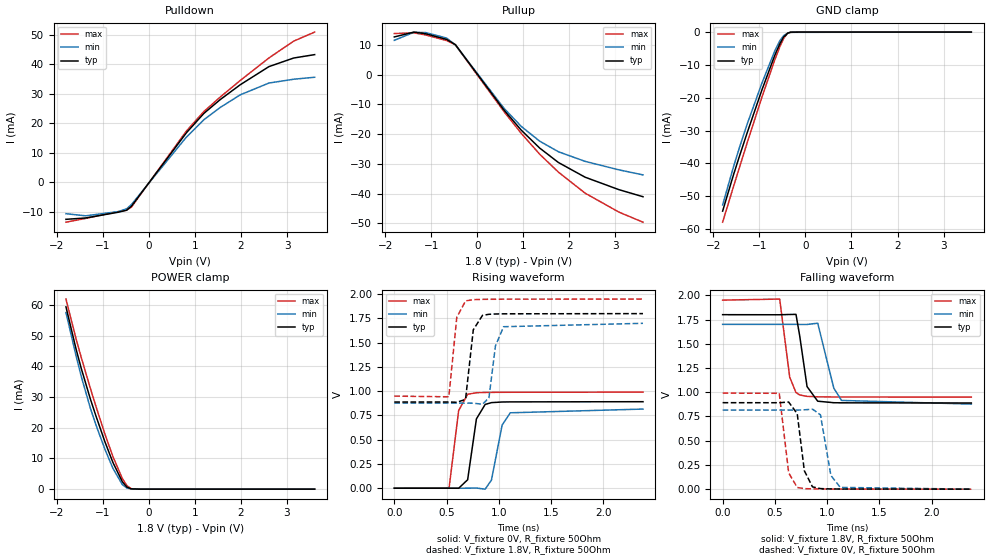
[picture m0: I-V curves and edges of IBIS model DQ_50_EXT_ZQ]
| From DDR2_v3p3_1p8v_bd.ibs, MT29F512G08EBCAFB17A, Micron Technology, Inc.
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| MODEL DQ_50_EXT_ZQ (50 Ohm Data I/O with no ODT, With ZQ Cal)
[Model]   DQ_50_EXT_ZQ
Model_type   I/O
Vinl = 650.000mV
Vinh = 1.150V
Vmeas = 900.000mV
Vref = 900.000mV
Cref = 0.0pF
Rref = 50.000Ohm
|   typ   min   max
|C_comp   1.200pF   1.100pF   1.300pF
C_comp_pullup   0.6000pF   0.5500pF   0.6500pF
C_comp_pulldown   0.6000pF   0.5500pF   0.6500pF
[Model Spec]
| Input threshold voltage corners
Vinl   0.6500V   0.6000V   0.7250V
Vinh   1.1500V   1.1000V   1.2250V
| Measurement voltage corners
Vmeas   0.9000V   0.8500V   0.9750V
| Timing spec test load voltage corners
Vref   0.9000V   0.8500V   0.9750V
| Dynamic Overshoot Parameters from ONFI4 Specification
D_overshoot_ampl_h   1.00   NA   NA
D_overshoot_ampl_l   1.00   NA   NA
D_overshoot_area_h   0.75n   NA   NA
D_overshoot_area_l   0.75n   NA   NA
[Receiver Thresholds]
Vth   =  0.900V
Vth_min  =  0.8820V
Vth_max  =  0.9180V
Vinh_ac  =  0.250V
Vinh_dc  =  0.125V
Vinl_ac  = -0.250V
Vinl_dc  = -0.125V
Tslew_ac =  5.000ns |Not specified, so set to high value
Threshold_sensitivity = 0.50
Reference_supply Pullup_ref
[Voltage Range]   1.8000V   1.7000V   1.9500V
[Pullup Reference]   1.8000V   1.7000V   1.9500V
| Junction Temperature (Ambient temp is 35C typ, 70C min, 0C max)
[Temperature Range]   50.0   85.0   0.0
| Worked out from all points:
|   slope of the pulldown table from 0 to 0.27 V, typ, clamps not added: 46.9 ohm
|   slope of the pullup table from 0 to 0.27 V, typ, clamps not added: 47.2 ohm
|   GND clamp passes 1 mA (typ) near -0.45 V on its own axis
|   POWER clamp passes 1 mA (typ) near -0.50 V on its own axis
|   falling waveform, V_fixture 1.8V, R_fixture 50Ohm: 20-80 % time 71.5ps typ, 80.7ps min, 66.5ps max; typ from 1.8 V to 0.889 V
|   rising waveform, V_fixture 0V, R_fixture 50Ohm: 20-80 % time 70.2ps typ, 87.8ps min, 56.8ps max; typ from 0 V to 0.892 V
|   rising waveform, V_fixture 1.8V, R_fixture 50Ohm: 20-80 % time 50.3ps typ, 58.8ps min, 43.2ps max; typ from 0.889 V to 1.8 V
|   falling waveform, V_fixture 0V, R_fixture 50Ohm: 20-80 % time 62.9ps typ, 71.3ps min, 56.4ps max; typ from 0.892 V to 0 V
[Pulldown]
|   Voltage   I(typ)   I(min)   I(max)
-1.8V     -12.5mA    -10.59mA   -13.47mA
-1.372V   -12.04mA   -11.31mA   -12.19mA
-667.8mV  -10.1mA    -9.89mA    -9.893mA
-482.4mV  -9.42mA    -8.93mA    -9.36mA
-380.4mV  -8.076mA   -7.521mA   -8.376mA
813mV     16.79mA    15.34mA    17.4mA
1.195V    23.42mA    21.27mA    24.05mA
1.548V    28.08mA    25.41mA    28.94mA
1.985V    33.13mA    29.71mA    34.58mA
2.608V    39.28mA    33.71mA    42.22mA
3.145V    42.19mA    35mA       47.92mA
3.6V      43.34mA    35.67mA    50.98mA
[GND Clamp]
|   Voltage   I(typ)   I(min)   I(max)
-1.8V     -54.56mA   -52.69mA   -57.93mA
-1.562V   -43.4mA    -40.96mA   -46.99mA
-1.429V   -37.59mA   -34.94mA   -41mA
-1.266V   -30.66mA   -28.02mA   -33.7mA
-947.8mV  -17.69mA   -15.6mA    -19.91mA
-667.8mV  -7.119mA   -5.754mA   -8.475mA
-553.9mV  -3.463mA   -2.548mA   -4.387mA
-474mV    -1.491mA   -1.087mA   -1.954mA
-382.4mV  -312.7uA   -236.9uA   -256.7uA
-322.2mV  -17.1uA    -73.07uA   -96.02uA
-163.8mV  -610.8nA   -69.45uA   -682.8nA
3.604V    0A         0A         0A
[Pullup]
|   Voltage   I(typ)   I(min)   I(max)
-1.8V     12.64mA    11.51mA    13.78mA
-1.373V   14.27mA    14.2mA     14.02mA
-1.117V   13.71mA    14.1mA     13.3mA
-666.1mV  11.81mA    12.27mA    11.43mA
-474mV    10.06mA    9.995mA    9.971mA
586.8mV   -12.02mA   -11.42mA   -12.54mA
959.3mV   -18.72mA   -17.45mA   -19.81mA
1.355V    -24.67mA   -22.36mA   -26.72mA
1.765V    -29.56mA   -25.94mA   -32.8mA
2.344V    -34.49mA   -29.17mA   -39.85mA
3.076V    -38.66mA   -32.01mA   -46.2mA
3.6V      -41.04mA   -33.71mA   -49.6mA
[POWER Clamp]
|   Voltage   I(typ)   I(min)   I(max)
-1.8V     59.37mA    57.52mA    61.9mA
-1.582V   45.72mA    43.5mA     49.03mA
-1.467V   39.27mA    36.67mA    42.84mA
-1.27V    29.38mA    26.39mA    32.83mA
-1.145V   23.68mA    20.79mA    26.82mA
-951.7mV  15.36mA    12.93mA    17.84mA
-780mV    8.708mA    6.801mA    10.63mA
-575.4mV  2.436mA    1.5mA      3.454mA
-473.4mV  660.1uA    347.9uA    1.122mA
-380.4mV  103uA      53.11uA    144.5uA
-178.2mV  714nA      0A         668.1nA
3.604V    0A         0A         0A
[Ramp]
R_load = 50
|   typ   min   max
dV/dt_r 5.3523E-01/7.0073E-11   4.8949E-01/8.7642E-11   5.9441E-01/5.6465E-11
dV/dt_f 5.4672E-01/7.1373E-11   4.9338E-01/8.0346E-11   6.0023E-01/6.6470E-11
[Falling Waveform]
V_fixture = 1.8V
V_fixture_min = 1.7V
V_fixture_max = 1.95V
R_fixture = 50Ohm
C_fixture = 0F
|   Time   V(typ)   V(min)   V(max)
0s        1.8V       1.7V       1.95V
546ps     1.799V     1.7V       1.961V
642ps     1.802V     1.7V       1.155V
702ps     1.803V     1.7V       997mV
738ps     1.579V     1.699V     971.9mV
808ps     1.058V     1.699V     957.3mV
910ps     907.4mV    1.712V     952.6mV
1.064ns   891.8mV    1.042V     951mV
1.138ns   890.7mV    915.3mV    950.6mV
2.38ns    888.8mV    877.7mV    949.6mV
[Rising Waveform]
V_fixture = 0V
V_fixture_min = 0V
V_fixture_max = 0V
R_fixture = 50Ohm
C_fixture = 0F
|   Time   V(typ)   V(min)   V(max)
0s        85.53uV    160.9uV    26.43uV
524ps     520.4uV    114uV      108.1uV
616ps     -68.01uV   65.56uV    801.2mV
702ps     87.56mV    527.1uV    968.7mV
786ps     715.2mV    1.802mV    984.6mV
870ps     864.1mV    -9.573mV   987.4mV
930ps     882.4mV    85.27mV    988.2mV
1.032ns   888.9mV    651.5mV    989mV
1.11ns    890.1mV    777.6mV    989.4mV
2.38ns    892.1mV    816mV      990.7mV
[Rising Waveform]
V_fixture = 1.8V
V_fixture_min = 1.7V
V_fixture_max = 1.95V
R_fixture = 50Ohm
C_fixture = 0F
|   Time   V(typ)   V(min)   V(max)
0s        888.7mV    877.5mV    949.6mV
522ps     889mV      877.5mV    942.5mV
598ps     885.9mV    877.3mV    1.761V
682ps     916.2mV    877.5mV    1.931V
756ps     1.633V     876.7mV    1.944V
844ps     1.782V     866mV      1.947V
906ps     1.793V     932.4mV    1.948V
968ps     1.796V     1.467V     1.948V
1.046ns   1.798V     1.665V     1.949V
2.38ns    1.8V       1.7V       1.95V
[Falling Waveform]
|Gnd
V_fixture = 0V
V_fixture_min = 0V
V_fixture_max = 0V
R_fixture = 50Ohm
C_fixture = 0F
|   Time   V(typ)   V(min)   V(max)
0s        892.2mV    816.1mV    990.7mV
542ps     891.7mV    816.2mV    989mV
632ps     898.8mV    816.2mV    168.4mV
714ps     778.2mV    815.6mV    17.52mV
782ps     190.2mV    818.6mV    5.884mV
860ps     23.7mV     825.1mV    3.075mV
936ps     5.966mV    767.4mV    2.07mV
1.036ns   2.469mV    141.3mV    1.466mV
1.126ns   1.606mV    18.23mV    1.119mV
2.38ns    172.1uV    287uV      83.88uV
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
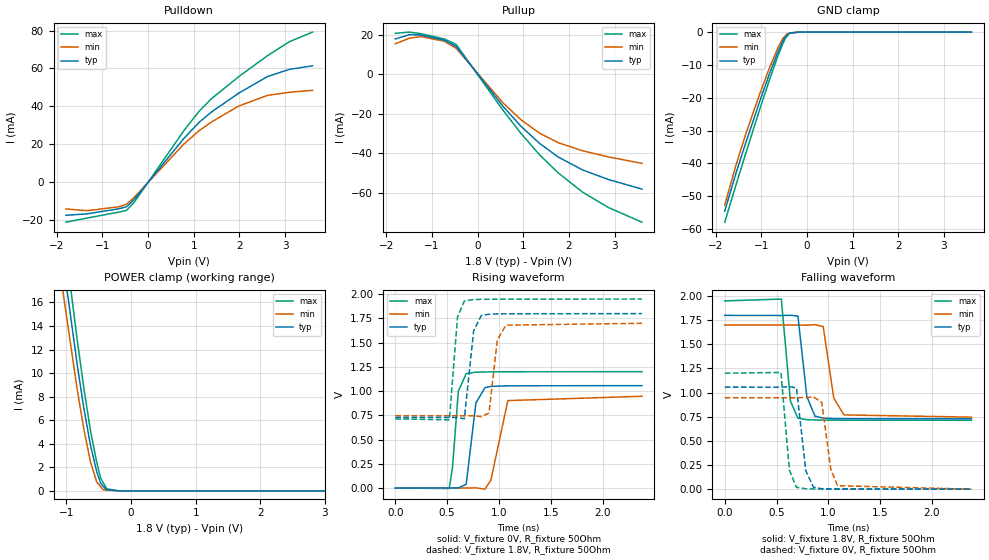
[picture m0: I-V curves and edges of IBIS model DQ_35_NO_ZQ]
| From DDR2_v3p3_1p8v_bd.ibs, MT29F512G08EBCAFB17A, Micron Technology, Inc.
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| MODEL DQ_35_NO_ZQ (35 Ohm Data I/O with no ODT, With No Cal)
[Model]   DQ_35_NO_ZQ
Model_type   I/O
Vinl = 650.000mV
Vinh = 1.150V
Vmeas = 900.000mV
Vref = 900.000mV
Cref = 0.0pF
Rref = 50.000Ohm
|   typ   min   max
|C_comp   1.200pF   1.100pF   1.300pF
C_comp_pullup   0.6000pF   0.5500pF   0.6500pF
C_comp_pulldown   0.6000pF   0.5500pF   0.6500pF
[Model Spec]
| Input threshold voltage corners
Vinl   0.6500V   0.6000V   0.7250V
Vinh   1.1500V   1.1000V   1.2250V
| Measurement voltage corners
Vmeas   0.9000V   0.8500V   0.9750V
| Timing spec test load voltage corners
Vref   0.9000V   0.8500V   0.9750V
| Dynamic Overshoot Parameters from ONFI4 Specification
D_overshoot_ampl_h   1.00   NA   NA
D_overshoot_ampl_l   1.00   NA   NA
D_overshoot_area_h   0.75n   NA   NA
D_overshoot_area_l   0.75n   NA   NA
[Receiver Thresholds]
Vth   =  0.900V
Vth_min  =  0.8820V
Vth_max  =  0.9180V
Vinh_ac  =  0.250V
Vinh_dc  =  0.125V
Vinl_ac  = -0.250V
Vinl_dc  = -0.125V
Tslew_ac =  5.000ns |Not specified, so set to high value
Threshold_sensitivity = 0.50
Reference_supply Pullup_ref
[Voltage Range]   1.8000V   1.7000V   1.9500V
[Pullup Reference]   1.8000V   1.7000V   1.9500V
| Junction Temperature (Ambient temp is 35C typ, 70C min, 0C max)
[Temperature Range]   50.0   85.0   0.0
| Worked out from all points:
|   slope of the pulldown table from 0 to 0.27 V, typ, clamps not added: 33.1 ohm
|   slope of the pullup table from 0 to 0.27 V, typ, clamps not added: 33.4 ohm
|   GND clamp passes 1 mA (typ) near -0.44 V on its own axis
|   POWER clamp passes 1 mA (typ) near -0.50 V on its own axis
|   falling waveform, V_fixture 1.8V, R_fixture 50Ohm: 20-80 % time 62.7ps typ, 74.2ps min, 53.7ps max; typ from 1.8 V to 0.728 V
|   rising waveform, V_fixture 0V, R_fixture 50Ohm: 20-80 % time 61.4ps typ, 78.4ps min, 49.4ps max; typ from 0 V to 1.06 V
|   rising waveform, V_fixture 1.8V, R_fixture 50Ohm: 20-80 % time 44.4ps typ, 52.3ps min, 38ps max; typ from 0.728 V to 1.8 V
|   falling waveform, V_fixture 0V, R_fixture 50Ohm: 20-80 % time 58ps typ, 68.5ps min, 50.1ps max; typ from 1.06 V to 0 V
[Pulldown]
|   Voltage   I(typ)   I(min)   I(max)
-1.8V     -17.7mA    -14.36mA   -21.34mA
-1.331V   -16.91mA   -15.24mA   -19.12mA
-630.4mV  -14.2mA    -13.16mA   -15.98mA
-473.4mV  -13.2mA    -11.88mA   -15.08mA
-313.2mV  -9.601mA   -8.423mA   -11.12mA
776mV     22.77mA    19.79mA    26.8mA
1.116V    31.44mA    27.04mA    37.31mA
1.394V    37.03mA    31.74mA    44.1mA
1.985V    46.91mA    40.09mA    55.61mA
2.614V    55.67mA    45.71mA    66.71mA
3.092V    59.47mA    47.35mA    74.09mA
3.6V      61.35mA    48.4mA     79.18mA
[GND Clamp]
|   Voltage   I(typ)   I(min)   I(max)
-1.8V     -54.56mA   -52.69mA   -57.93mA
-1.554V   -43.01mA   -40.54mA   -46.59mA
-1.336V   -33.61mA   -30.93mA   -36.81mA
-1.036V   -21.2mA    -18.93mA   -23.66mA
-829.3mV  -13.08mA   -11.23mA   -14.95mA
-630.4mV  -5.889mA   -4.612mA   -7.067mA
-531.8mV  -2.931mA   -2.046mA   -3.69mA
-472.1mV  -1.487mA   -1.111mA   -1.902mA
-431.5mV  -903.3uA   -483.2uA   -1.222mA
-378mV    -285.6uA   -293uA     -327uA
-178.2mV  -2.719uA   -1.561uA   -751.9nA
3.604V    0A         0A         0A
[Pullup]
|   Voltage   I(typ)   I(min)   I(max)
-1.8V     17.84mA    15.4mA     20.68mA
-1.492V   20.03mA    18.23mA    21.32mA
-1.242V   19.84mA    19.05mA    20.53mA
-729mV    17.17mA    16.69mA    17.85mA
-472.1mV  14.17mA    13.21mA    15.18mA
564.7mV   -16.42mA   -14.66mA   -18.41mA
957.4mV   -26.46mA   -23.16mA   -30.13mA
1.359V    -35mA      -29.83mA   -40.79mA
1.765V    -41.86mA   -34.62mA   -49.89mA
2.301V    -48.43mA   -38.72mA   -59.68mA
2.866V    -53.25mA   -41.82mA   -67.44mA
3.6V      -58.12mA   -45.09mA   -74.85mA
[POWER Clamp]
|   Voltage   I(typ)   I(min)   I(max)
-1.8V     59.37mA    57.52mA    61.9mA
-1.055V   19.69mA    17mA       22.54mA
-1.034V   18.79mA    16.14mA    21.56mA
-829.3mV  10.55mA    8.462mA    12.64mA
-729mV    6.964mA    5.185mA    8.66mA
-630.4mV  3.937mA    2.522mA    5.201mA
-531mV    1.618mA    753.4uA    2.409mA
-472.1mV  669.5uA    367.5uA    1.103mA
-431.5mV  391.1uA    106.3uA    708.2uA
-376.5mV  100.3uA    62.6uA     180.1uA
-178.2mV  0A         501.6nA    561.5nA
3.604V    0A         0A         0A
[Ramp]
R_load = 50
|   typ   min   max
dV/dt_r 6.3425E-01/6.1156E-11   5.6816E-01/7.7489E-11   7.2087E-01/4.9145E-11
dV/dt_f 6.4316E-01/6.2537E-11   5.7228E-01/7.3865E-11   7.4183E-01/5.3549E-11
[Falling Waveform]
V_fixture = 1.8V
V_fixture_min = 1.7V
V_fixture_max = 1.95V
R_fixture = 50Ohm
C_fixture = 0F
|   Time   V(typ)   V(min)   V(max)
0s        1.8V       1.7V       1.95V
546ps     1.799V     1.7V       1.969V
634ps     1.801V     1.7V       911.8mV
706ps     1.793V     1.7V       735.2mV
792ps     960.4mV    1.698V     719.1mV
870ps     756.6mV    1.704V     716.6mV
950ps     735.4mV    1.684V     715.5mV
1.052ns   730.9mV    943.2mV    714.8mV
1.15ns    729.7mV    769.2mV    714.4mV
2.38ns    728.1mV    746.1mV    713.6mV
[Rising Waveform]
V_fixture = 0V
V_fixture_min = 0V
V_fixture_max = 0V
R_fixture = 50Ohm
C_fixture = 0F
|   Time   V(typ)   V(min)   V(max)
0s        77.71uV    151uV      22.52uV
520ps     407uV      107.6uV    -4.55mV
552ps     1.505mV    105uV      213.2mV
608ps     1.597mV    70.13uV    998.6mV
684ps     38.38mV    162.8uV    1.181V
778ps     879.3mV    2.272mV    1.196V
866ps     1.037V     -11.36mV   1.198V
922ps     1.049V     81.9mV     1.199V
1.086ns   1.055V     902.5mV    1.2V
2.38ns    1.057V     947.1mV    1.201V
[Rising Waveform]
V_fixture = 1.8V
V_fixture_min = 1.7V
V_fixture_max = 1.95V
R_fixture = 50Ohm
C_fixture = 0F
|   Time   V(typ)   V(min)   V(max)
0s        728mV      746mV      713.6mV
522ps     728.3mV    746mV      704.2mV
600ps     726.8mV    745.9mV    1.764V
666ps     715.3mV    745.9mV    1.93V
756ps     1.623V     746.3mV    1.945V
830ps     1.78V      737.5mV    1.947V
904ps     1.794V     774.2mV    1.948V
984ps     1.797V     1.527V     1.948V
1.068ns   1.798V     1.681V     1.949V
2.38ns    1.8V       1.7V       1.95V
[Falling Waveform]
|Gnd
V_fixture = 0V
V_fixture_min = 0V
V_fixture_max = 0V
R_fixture = 50Ohm
C_fixture = 0F
|   Time   V(typ)   V(min)   V(max)
0s        1.057V     947.2mV    1.201V
542ps     1.056V     947.3mV    1.209V
624ps     1.062V     947.3mV    198.2mV
692ps     1.05V      946.9mV    19.04mV
782ps     191.3mV    948.4mV    4.38mV
856ps     20.36mV    956.1mV    2.688mV
936ps     4.976mV    897.5mV    1.813mV
1.024ns   2.434mV    204.2mV    1.316mV
1.088ns   1.772mV    35.8mV     1.078mV
2.38ns    156.7uV    268.8uV    64.47uV
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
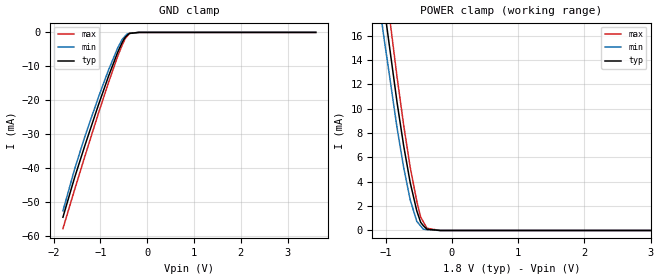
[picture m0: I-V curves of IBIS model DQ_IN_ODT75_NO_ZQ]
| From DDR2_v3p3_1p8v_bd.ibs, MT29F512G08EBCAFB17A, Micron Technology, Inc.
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| MODEL DQ_IN_ODT75_NO_ZQ (Data Input with 75ohm ODT, With No Cal)
[Model]   DQ_IN_ODT75_NO_ZQ
Model_type   Input
Vinl = 650.000mV
Vinh = 1.150V
|   typ   min   max
|C_comp   1.136pF   1.026pF   1.246pF
C_comp_power_clamp   0.5680pF   0.5130pF   0.6230pF
C_comp_gnd_clamp   0.5680pF   0.5130pF   0.6230pF
| Note: C_comp changes when the ODT circuit is enabled.
[Model Spec]
| Input threshold voltage corners
Vinl   0.6500V   0.6000V   0.7250V
Vinh   1.1500V   1.1000V   1.2250V
| Dynamic Overshoot Parameters from ONFI4 Specification
D_overshoot_ampl_h   1.00   NA   NA
D_overshoot_ampl_l   1.00   NA   NA
D_overshoot_area_h   0.75n   NA   NA
D_overshoot_area_l   0.75n   NA   NA
[Receiver Thresholds]
Vth   =  0.900V
Vth_min  =  0.8820V
Vth_max  =  0.9180V
Vinh_ac  =  0.250V
Vinh_dc  =  0.125V
Vinl_ac  = -0.250V
Vinl_dc  = -0.125V
Tslew_ac =  5.000ns |Not specified, so set to high value
Threshold_sensitivity = 0.50
Reference_supply Power_clamp_ref
[Voltage Range]   1.8000V   1.7000V   1.9500V
[POWER Clamp Reference]   1.8000V   1.7000V   1.9500V
| Junction Temperature (Ambient temp is 35C typ, 70C min, 0C max)
[Temperature Range]   50.0   85.0   0.0
[Add Submodel]
| Submodel Name   Mode
75ohm_ODT_NO_ZQ   Non-Driving
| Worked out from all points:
|   GND clamp passes 1 mA (typ) near -0.44 V on its own axis
|   POWER clamp passes 1 mA (typ) near -0.50 V on its own axis
[GND Clamp]
|   Voltage   I(typ)   I(min)   I(max)
-1.8V     -54.56mA   -52.69mA   -57.93mA
-1.554V   -43.01mA   -40.54mA   -46.59mA
-1.336V   -33.61mA   -30.93mA   -36.81mA
-1.036V   -21.2mA    -18.93mA   -23.66mA
-829.3mV  -13.08mA   -11.23mA   -14.95mA
-630.4mV  -5.889mA   -4.612mA   -7.067mA
-531.8mV  -2.931mA   -2.046mA   -3.69mA
-472.1mV  -1.487mA   -1.111mA   -1.902mA
-431.5mV  -903.3uA   -483.2uA   -1.222mA
-378mV    -285.6uA   -293uA     -327uA
-178.2mV  -2.719uA   -1.561uA   -751.9nA
3.604V    0A         0A         0A
[POWER Clamp]
|   Voltage   I(typ)   I(min)   I(max)
-1.8V     59.37mA    57.52mA    61.9mA
-1.055V   19.69mA    17mA       22.54mA
-1.034V   18.79mA    16.14mA    21.56mA
-829.3mV  10.55mA    8.462mA    12.64mA
-729mV    6.964mA    5.185mA    8.66mA
-630.4mV  3.937mA    2.522mA    5.201mA
-531mV    1.618mA    753.4uA    2.409mA
-472.1mV  669.5uA    367.5uA    1.103mA
-431.5mV  391.1uA    106.3uA    708.2uA
-376.5mV  100.3uA    62.6uA     180.1uA
-178.2mV  0A         501.6nA    561.5nA
3.604V    0A         0A         0A
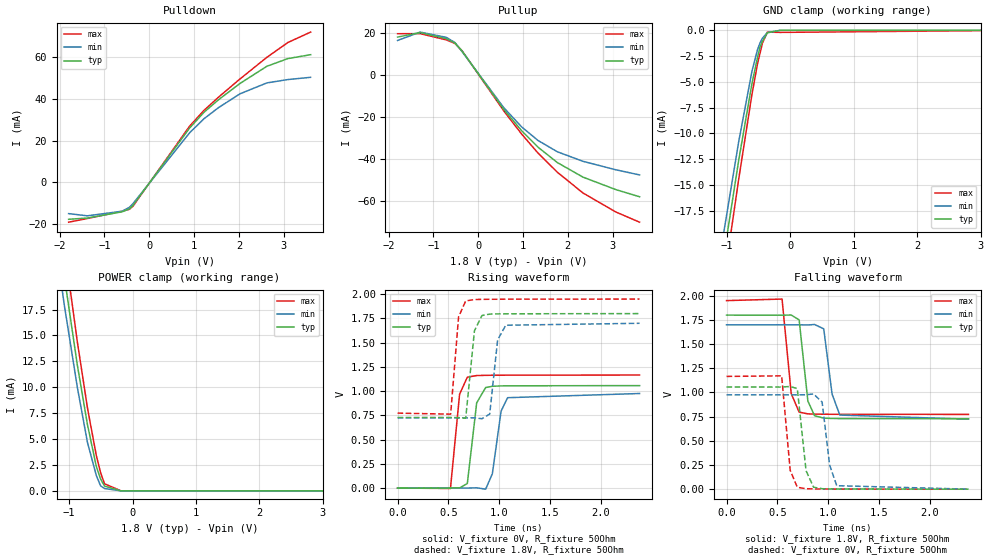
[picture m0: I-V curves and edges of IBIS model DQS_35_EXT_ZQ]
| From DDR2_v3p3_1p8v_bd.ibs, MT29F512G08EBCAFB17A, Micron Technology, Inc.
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| MODEL DQS_35_EXT_ZQ (35 Ohm Data Strobe I/O with no ODT, With ZQ Cal)
[Model]   DQS_35_EXT_ZQ
Model_type   I/O
Vinl = 650.000mV
Vinh = 1.150V
Vmeas = 900.000mV
Vref = 900.000mV
Cref = 0.0pF
Rref = 50.000Ohm
|   typ   min   max
|C_comp   1.200pF   1.100pF   1.300pF
C_comp_pullup   0.6000pF   0.5500pF   0.6500pF
C_comp_pulldown   0.6000pF   0.5500pF   0.6500pF
[Model Spec]
| Input threshold voltage corners
Vinl   0.6500V   0.6000V   0.7250V
Vinh   1.1500V   1.1000V   1.2250V
| Measurement voltage corners
Vmeas   0.9000V   0.8500V   0.9750V
| Timing spec test load voltage corners
Vref   0.9000V   0.8500V   0.9750V
| Dynamic Overshoot Parameters from ONFI4 Specification
D_overshoot_ampl_h   1.00   NA   NA
D_overshoot_ampl_l   1.00   NA   NA
D_overshoot_area_h   0.75n   NA   NA
D_overshoot_area_l   0.75n   NA   NA
[Receiver Thresholds]
|Vth   =  0.900V
|Vth_min  =  0.8820V
|Vth_max  =  0.9180V
|Vinh_ac  =  0.250V
|Vinh_dc  =  0.125V
|Vinl_ac  = -0.250V
|Vinl_dc  = -0.125V
|Tslew_ac =  5.000ns |Not specified, so set to high value
|Threshold_sensitivity = 0.50
|Reference_supply Pullup_ref
Vcross_low   = 0.725V
Vcross_high  = 1.075V
Vdiff_ac   = 500mV
Vdiff_dc   = 250mV
Tdiffslew_ac = 10.000ns |Not specified, so set to high value
[Voltage Range]   1.8000V   1.7000V   1.9500V
[Pullup Reference]   1.8000V   1.7000V   1.9500V
| Junction Temperature (Ambient temp is 35C typ, 70C min, 0C max)
[Temperature Range]   50.0   85.0   0.0
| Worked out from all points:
|   slope of the pulldown table from 0 to 0.27 V, typ, clamps not added: 33.1 ohm
|   slope of the pullup table from 0 to 0.27 V, typ, clamps not added: 33.4 ohm
|   GND clamp passes 1 mA (typ) near -0.44 V on its own axis
|   POWER clamp passes 1 mA (typ) near -0.50 V on its own axis
|   falling waveform, V_fixture 1.8V, R_fixture 50Ohm: 20-80 % time 63.1ps typ, 71ps min, 58.7ps max; typ from 1.8 V to 0.728 V
|   rising waveform, V_fixture 0V, R_fixture 50Ohm: 20-80 % time 61.4ps typ, 75.9ps min, 51.1ps max; typ from 0 V to 1.06 V
|   rising waveform, V_fixture 1.8V, R_fixture 50Ohm: 20-80 % time 44.4ps typ, 51.4ps min, 39.1ps max; typ from 0.728 V to 1.8 V
|   falling waveform, V_fixture 0V, R_fixture 50Ohm: 20-80 % time 58ps typ, 66.3ps min, 52ps max; typ from 1.06 V to 0 V
[Pulldown]
|   Voltage   I(typ)   I(min)   I(max)
-1.8V     -17.7mA    -14.98mA   -19.1mA
-1.382V   -17.11mA   -16.04mA   -17.33mA
-608.3mV  -14.13mA   -13.83mA   -13.84mA
-442.8mV  -12.67mA   -11.96mA   -12.9mA
-362.9mV  -10.97mA   -10.16mA   -11.4mA
901.3mV   26.16mA    23.87mA    27.08mA
1.224V    33.76mA    30.65mA    34.67mA
1.548V    39.76mA    35.96mA    41mA
2.021V    47.48mA    42.52mA    49.64mA
2.623V    55.77mA    47.79mA    60.05mA
3.092V    59.47mA    49.4mA     67.19mA
3.6V      61.35mA    50.48mA    72.2mA
[GND Clamp]
|   Voltage   I(typ)   I(min)   I(max)
-1.8V     -54.56mA   -52.69mA   -57.93mA
-1.548V   -42.78mA   -40.31mA   -46.36mA
-1.327V   -33.25mA   -30.57mA   -36.44mA
-1.077V   -22.86mA   -20.51mA   -25.43mA
-817.4mV  -12.62mA   -10.81mA   -14.45mA
-608.3mV  -5.168mA   -3.972mA   -6.219mA
-520.8mV  -2.645mA   -1.885mA   -3.256mA
-480.6mV  -1.611mA   -1.209mA   -2.217mA
-442.8mV  -1.066mA   -762.6uA   -1.241mA
-364.8mV  -238.2uA   -221uA     -173.5uA
-163.8mV  -972.9nA   0A         -201.1uA
3.604V    0A         0A         0A
[Pullup]
|   Voltage   I(typ)   I(min)   I(max)
-1.8V     17.84mA    16.24mA    19.44mA
-1.297V   20mA       20.22mA    19.5mA
-713.7mV  17.06mA    17.72mA    16.51mA
-520.8mV  15.03mA    15.26mA    14.81mA
-362.9mV  11.26mA    10.99mA    11.39mA
574.9mV   -16.7mA    -15.87mA   -17.41mA
971mV     -26.78mA   -24.94mA   -28.36mA
1.333V    -34.51mA   -31.33mA   -37.32mA
1.765V    -41.86mA   -36.72mA   -46.45mA
2.338V    -48.79mA   -41.26mA   -56.33mA
3.067V    -54.69mA   -45.27mA   -65.33mA
3.6V      -58.12mA   -47.73mA   -70.22mA
[POWER Clamp]
|   Voltage   I(typ)   I(min)   I(max)
-1.8V     59.37mA    57.52mA    61.9mA
-1.585V   45.91mA    43.7mA     49.21mA
-1.437V   37.69mA    35mA       41.3mA
-1.276V   29.7mA     26.71mA    33.17mA
-1.077V   20.68mA    17.92mA    23.6mA
-871.2mV  12.13mA    9.982mA    14.37mA
-712mV    6.399mA    4.675mA    8.008mA
-572.4mV  2.368mA    1.496mA    3.424mA
-504.6mV  1.145mA    486.6uA    1.765mA
-442.8mV  468.7uA    231.8uA    685.7uA
-178.2mV  0A         0A         0A
3.604V    0A         0A         0A
[Ramp]
R_load = 50
|   typ   min   max
dV/dt_r 6.3425E-01/6.1156E-11   5.8519E-01/7.5395E-11   6.9956E-01/5.0656E-11
dV/dt_f 6.4316E-01/6.2537E-11   5.8549E-01/7.0593E-11   7.0614E-01/5.8457E-11
[Falling Waveform]
V_fixture = 1.8V
V_fixture_min = 1.7V
V_fixture_max = 1.95V
R_fixture = 50Ohm
C_fixture = 0F
|   Time   V(typ)   V(min)   V(max)
0s        1.8V       1.7V       1.95V
546ps     1.799V     1.7V       1.966V
636ps     1.801V     1.7V       988.7mV
714ps     1.751V     1.7V       796.6mV
800ps     911mV      1.698V     778.8mV
866ps     759.3mV    1.703V     776.4mV
956ps     734.8mV    1.658V     775.1mV
1.038ns   731.2mV    983.7mV    774.4mV
1.114ns   730mV      766.3mV    774.1mV
2.38ns    728.1mV    724.1mV    773.1mV
[Rising Waveform]
V_fixture = 0V
V_fixture_min = 0V
V_fixture_max = 0V
R_fixture = 50Ohm
C_fixture = 0F
|   Time   V(typ)   V(min)   V(max)
0s        77.71uV    148.8uV    25.96uV
520ps     407uV      108.2uV    -4.379mV
610ps     1.34mV     67.12uV    969.2mV
686ps     46.66mV    216.9uV    1.144V
778ps     879.3mV    2.279mV    1.161V
866ps     1.037V     -11.54mV   1.163V
932ps     1.05V      146.7mV    1.164V
1.018ns   1.054V     793.6mV    1.164V
1.082ns   1.055V     932.3mV    1.165V
2.38ns    1.057V     975.5mV    1.166V
[Rising Waveform]
V_fixture = 1.8V
V_fixture_min = 1.7V
V_fixture_max = 1.95V
R_fixture = 50Ohm
C_fixture = 0F
|   Time   V(typ)   V(min)   V(max)
0s        728mV      724mV      773.1mV
522ps     728.3mV    724mV      762.5mV
600ps     726.8mV    723.8mV    1.766V
670ps     720.2mV    723.9mV    1.931V
756ps     1.623V     724.3mV    1.945V
830ps     1.78V      715.4mV    1.947V
906ps     1.795V     763.3mV    1.948V
984ps     1.797V     1.529V     1.948V
1.064ns   1.798V     1.68V      1.949V
2.38ns    1.8V       1.7V       1.95V
[Falling Waveform]
|Gnd
V_fixture = 0V
V_fixture_min = 0V
V_fixture_max = 0V
R_fixture = 50Ohm
C_fixture = 0F
|   Time   V(typ)   V(min)   V(max)
0s        1.057V     975.6mV    1.166V
542ps     1.056V     975.7mV    1.172V
626ps     1.062V     975.7mV    195mV
696ps     1.04V      975.2mV    19.77mV
782ps     191.3mV    977mV      4.814mV
856ps     20.36mV    984.4mV    2.815mV
940ps     4.792mV    900.3mV    1.923mV
1.014ns   2.602mV    250.1mV    1.443mV
1.084ns   1.808mV    35.79mV    1.154mV
2.38ns    156.7uV    262.2uV    75.18uV
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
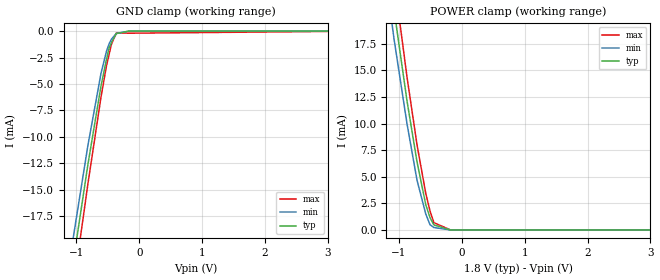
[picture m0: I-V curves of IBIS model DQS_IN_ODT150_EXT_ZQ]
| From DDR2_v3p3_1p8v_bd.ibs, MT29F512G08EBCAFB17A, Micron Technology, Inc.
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| MODEL DQS_IN_ODT150_EXT_ZQ (Data Strobe Input with 150ohm ODT, With ZQ Cal)
[Model]   DQS_IN_ODT150_EXT_ZQ
Model_type   Input
Vinl = 650.000mV
Vinh = 1.150V
|   typ   min   max
|C_comp   1.166pF   1.062pF   1.271pF
C_comp_power_clamp   0.5830pF   0.5310pF   0.6355pF
C_comp_gnd_clamp   0.5830pF   0.5310pF   0.6355pF
| Note: C_comp changes when the ODT circuit is enabled.
[Model Spec]
| Input threshold voltage corners
Vinl   0.6500V   0.6000V   0.7250V
Vinh   1.1500V   1.1000V   1.2250V
| Dynamic Overshoot Parameters from ONFI4 Specification
D_overshoot_ampl_h   1.00   NA   NA
D_overshoot_ampl_l   1.00   NA   NA
D_overshoot_area_h   0.75n   NA   NA
D_overshoot_area_l   0.75n   NA   NA
[Receiver Thresholds]
|Vth   =  0.900V
|Vth_min  =  0.8820V
|Vth_max  =  0.9180V
|Vinh_ac  =  0.250V
|Vinh_dc  =  0.125V
|Vinl_ac  = -0.250V
|Vinl_dc  = -0.125V
|Tslew_ac =  5.000ns |Not specified, so set to high value
|Threshold_sensitivity = 0.50
|Reference_supply Power_clamp_ref
Vcross_low   = 0.725V
Vcross_high  = 1.075V
Vdiff_ac   = 500mV
Vdiff_dc   = 250mV
Tdiffslew_ac = 10.000ns |Not specified, so set to high value
[Voltage Range]   1.8000V   1.7000V   1.9500V
[POWER Clamp Reference]   1.8000V   1.7000V   1.9500V
| Junction Temperature (Ambient temp is 35C typ, 70C min, 0C max)
[Temperature Range]   50.0   85.0   0.0
[Add Submodel]
| Submodel Name   Mode
150ohm_ODT_EXT_ZQ   Non-Driving
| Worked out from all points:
|   GND clamp passes 1 mA (typ) near -0.44 V on its own axis
|   POWER clamp passes 1 mA (typ) near -0.50 V on its own axis
[GND Clamp]
|   Voltage   I(typ)   I(min)   I(max)
-1.8V     -54.56mA   -52.69mA   -57.93mA
-1.548V   -42.78mA   -40.31mA   -46.36mA
-1.327V   -33.25mA   -30.57mA   -36.44mA
-1.077V   -22.86mA   -20.51mA   -25.43mA
-817.4mV  -12.62mA   -10.81mA   -14.45mA
-608.3mV  -5.168mA   -3.972mA   -6.219mA
-520.8mV  -2.645mA   -1.885mA   -3.256mA
-480.6mV  -1.611mA   -1.209mA   -2.217mA
-442.8mV  -1.066mA   -762.6uA   -1.241mA
-364.8mV  -238.2uA   -221uA     -173.5uA
-163.8mV  -972.9nA   0A         -201.1uA
3.604V    0A         0A         0A
[POWER Clamp]
|   Voltage   I(typ)   I(min)   I(max)
-1.8V     59.37mA    57.52mA    61.9mA
-1.585V   45.91mA    43.7mA     49.21mA
-1.437V   37.69mA    35mA       41.3mA
-1.276V   29.7mA     26.71mA    33.17mA
-1.077V   20.68mA    17.92mA    23.6mA
-871.2mV  12.13mA    9.982mA    14.37mA
-712mV    6.399mA    4.675mA    8.008mA
-572.4mV  2.368mA    1.496mA    3.424mA
-504.6mV  1.145mA    486.6uA    1.765mA
-442.8mV  468.7uA    231.8uA    685.7uA
-178.2mV  0A         0A         0A
3.604V    0A         0A         0A
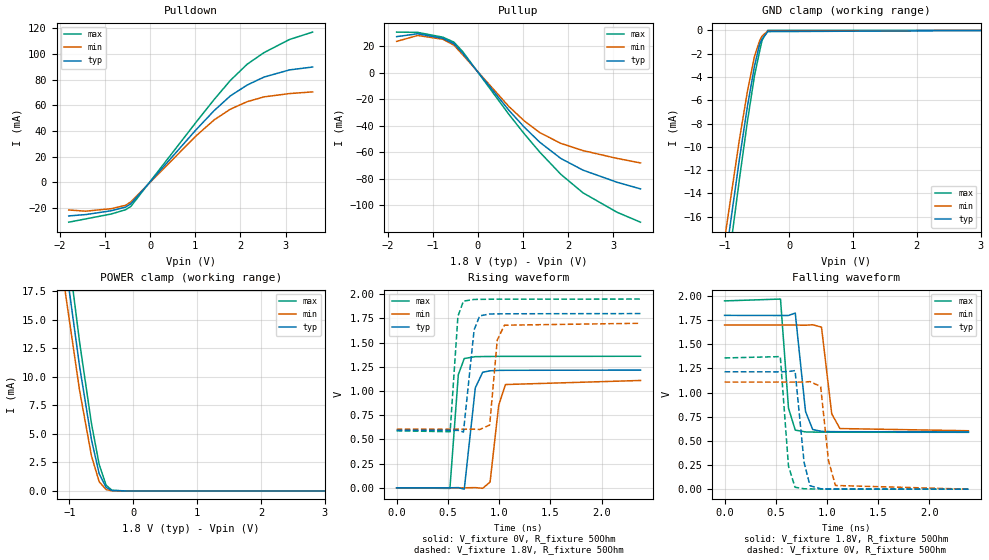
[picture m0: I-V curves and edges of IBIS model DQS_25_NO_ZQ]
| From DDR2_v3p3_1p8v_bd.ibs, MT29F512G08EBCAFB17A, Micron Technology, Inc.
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| MODEL DQS_25_NO_ZQ (25 Ohm Data Strobe I/O with no ODT, With No Cal)
[Model]   DQS_25_NO_ZQ
Model_type   I/O
Vinl = 650.000mV
Vinh = 1.150V
Vmeas = 900.000mV
Vref = 900.000mV
Cref = 0.0pF
Rref = 50.000Ohm
|   typ   min   max
|C_comp   1.200pF   1.100pF   1.300pF
C_comp_pullup   0.6000pF   0.5500pF   0.6500pF
C_comp_pulldown   0.6000pF   0.5500pF   0.6500pF
[Model Spec]
| Input threshold voltage corners
Vinl   0.6500V   0.6000V   0.7250V
Vinh   1.1500V   1.1000V   1.2250V
| Measurement voltage corners
Vmeas   0.9000V   0.8500V   0.9750V
| Timing spec test load voltage corners
Vref   0.9000V   0.8500V   0.9750V
| Dynamic Overshoot Parameters from ONFI4 Specification
D_overshoot_ampl_h   1.00   NA   NA
D_overshoot_ampl_l   1.00   NA   NA
D_overshoot_area_h   0.75n   NA   NA
D_overshoot_area_l   0.75n   NA   NA
[Receiver Thresholds]
|Vth   =  0.900V
|Vth_min  =  0.8820V
|Vth_max  =  0.9180V
|Vinh_ac  =  0.250V
|Vinh_dc  =  0.125V
|Vinl_ac  = -0.250V
|Vinl_dc  = -0.125V
|Tslew_ac =  5.000ns |Not specified, so set to high value
|Threshold_sensitivity = 0.50
|Reference_supply Pullup_ref
Vcross_low   = 0.725V
Vcross_high  = 1.075V
Vdiff_ac   = 500mV
Vdiff_dc   = 250mV
Tdiffslew_ac = 10.000ns |Not specified, so set to high value
[Voltage Range]   1.8000V   1.7000V   1.9500V
[Pullup Reference]   1.8000V   1.7000V   1.9500V
| Junction Temperature (Ambient temp is 35C typ, 70C min, 0C max)
[Temperature Range]   50.0   85.0   0.0
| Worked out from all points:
|   slope of the pulldown table from 0 to 0.27 V, typ, clamps not added: 24.4 ohm
|   slope of the pullup table from 0 to 0.27 V, typ, clamps not added: 23.5 ohm
|   GND clamp passes 1 mA (typ) near -0.44 V on its own axis
|   POWER clamp passes 1 mA (typ) near -0.50 V on its own axis
|   falling waveform, V_fixture 1.8V, R_fixture 50Ohm: 20-80 % time 56.2ps typ, 65.1ps min, 49.5ps max; typ from 1.8 V to 0.594 V
|   rising waveform, V_fixture 0V, R_fixture 50Ohm: 20-80 % time 51ps typ, 63.2ps min, 43.2ps max; typ from 0 V to 1.22 V
|   rising waveform, V_fixture 1.8V, R_fixture 50Ohm: 20-80 % time 39.1ps typ, 44.9ps min, 36ps max; typ from 0.593 V to 1.8 V
|   falling waveform, V_fixture 0V, R_fixture 50Ohm: 20-80 % time 56.5ps typ, 64.5ps min, 50.7ps max; typ from 1.22 V to 0 V
[Pulldown]
|   Voltage   I(typ)   I(min)   I(max)
-1.8V     -26.36mA   -21.71mA   -31.25mA
-1.426V   -25.32mA   -22.66mA   -28.71mA
-858.6mV  -22.32mA   -20.7mA    -24.85mA
-540.3mV  -19.51mA   -18.09mA   -21.53mA
-423.3mV  -16.83mA   -15.34mA   -18.93mA
1.018V    40.81mA    36.06mA    46.68mA
1.418V    55.76mA    48.52mA    64.39mA
1.778V    67.29mA    56.91mA    79.34mA
2.153V    75.82mA    62.82mA    92.08mA
2.525V    82mA       66.54mA    101.1mA
3.087V    87.58mA    69.12mA    111.3mA
3.6V      89.84mA    70.44mA    117.1mA
[GND Clamp]
|   Voltage   I(typ)   I(min)   I(max)
-1.8V     -54.56mA   -52.69mA   -57.93mA
-1.655V   -47.63mA   -45.42mA   -51.23mA
-1.426V   -37.44mA   -34.79mA   -40.84mA
-1.251V   -30.05mA   -27.42mA   -33.05mA
-1.033V   -21.1mA    -18.84mA   -23.56mA
-776.6mV  -11.06mA   -9.371mA   -12.78mA
-652.5mV  -6.574mA   -5.277mA   -7.868mA
-540.3mV  -3.062mA   -2.234mA   -3.888mA
-460.8mV  -1.227mA   -897.2uA   -1.819mA
-421.4mV  -732.2uA   -483.9uA   -851.1uA
-331.7mV  -111.2uA   -68.27uA   0A
3.604V    0A         0A         0A
[Pullup]
|   Voltage   I(typ)   I(min)   I(max)
-1.8V     27.24mA    23.66mA    30.68mA
-1.334V   29.42mA    28.12mA    30.45mA
-776.6mV  25.92mA    25.27mA    26.84mA
-530.5mV  21.9mA     20.81mA    23.08mA
-331.7mV  14.49mA    13.38mA    15.74mA
685.4mV   -28.28mA   -25.45mA   -31.37mA
1.025V    -40.97mA   -36.25mA   -45.99mA
1.369V    -52.39mA   -45.13mA   -59.85mA
1.835V    -64.62mA   -53.25mA   -76.58mA
2.326V    -73.43mA   -58.68mA   -90.53mA
3.08V     -82.57mA   -64.59mA   -105.2mA
3.6V      -87.58mA   -67.99mA   -112.7mA
[POWER Clamp]
|   Voltage   I(typ)   I(min)   I(max)
-1.8V     59.37mA    57.52mA    61.9mA
-1.584V   45.79mA    43.58mA    49.1mA
-1.443V   38mA       35.32mA    41.59mA
-1.319V   31.77mA    28.81mA    35.31mA
-1.1V     21.65mA    18.84mA    24.63mA
-839.5mV  10.93mA    8.816mA    13.05mA
-652.5mV  4.475mA    3.057mA    5.883mA
-532.5mV  1.513mA    808.8uA    2.325mA
-423.3mV  303uA      116uA      496.1uA
-331.7mV  35.79uA    6.866uA    57.43uA
-117.2mV  0A         135.7nA    0A
3.604V    0A         0A         0A
[Ramp]
R_load = 50
|   typ   min   max
dV/dt_r 7.2933E-01/5.0947E-11   6.6532E-01/6.2711E-11   8.1546E-01/4.3111E-11
dV/dt_f 7.2388E-01/5.5805E-11   6.5691E-01/6.4336E-11   8.1665E-01/4.9278E-11
[Falling Waveform]
V_fixture = 1.8V
V_fixture_min = 1.7V
V_fixture_max = 1.95V
R_fixture = 50Ohm
C_fixture = 0F
|   Time   V(typ)   V(min)   V(max)
0s        1.8V       1.7V       1.95V
546ps     1.799V     1.7V       1.969V
624ps     1.799V     1.7V       839mV
690ps     1.824V     1.7V       611.7mV
790ps     805.5mV    1.698V     593.1mV
860ps     618.1mV    1.703V     591.4mV
946ps     599mV      1.678V     590.5mV
1.046ns   595.9mV    779.9mV    589.9mV
1.126ns   595.1mV    627.9mV    589.7mV
2.38ns    593.5mV    605.1mV    588.9mV
[Rising Waveform]
V_fixture = 0V
V_fixture_min = 0V
V_fixture_max = 0V
R_fixture = 50Ohm
C_fixture = 0F
|   Time   V(typ)   V(min)   V(max)
0s        71.16uV    138.3uV    18.44uV
520ps     362.7uV    98.95uV    -6.003mV
602ps     2.039mV    63.41uV    1.169V
660ps     -13.92mV   31.2uV     1.336V
768ps     1.034V     2.16mV     1.355V
840ps     1.194V     -5.155mV   1.356V
912ps     1.209V     60.39mV    1.357V
996ps     1.213V     852.7mV    1.358V
1.062ns   1.214V     1.067V     1.358V
2.38ns    1.216V     1.109V     1.359V
[Rising Waveform]
V_fixture = 1.8V
V_fixture_min = 1.7V
V_fixture_max = 1.95V
R_fixture = 50Ohm
C_fixture = 0F
|   Time   V(typ)   V(min)   V(max)
0s        593.5mV    605mV      588.9mV
522ps     593.8mV    605mV      579.8mV
598ps     593.8mV    604.9mV    1.772V
652ps     576.4mV    604.9mV    1.929V
756ps     1.632V     605.8mV    1.946V
810ps     1.776V     602.2mV    1.947V
908ps     1.796V     648.4mV    1.948V
982ps     1.797V     1.527V     1.949V
1.052ns   1.798V     1.68V      1.949V
2.38ns    1.8V       1.7V       1.95V
[Falling Waveform]
|Gnd
V_fixture = 0V
V_fixture_min = 0V
V_fixture_max = 0V
R_fixture = 50Ohm
C_fixture = 0F
|   Time   V(typ)   V(min)   V(max)
0s        1.216V     1.109V     1.359V
544ps     1.215V     1.109V     1.373V
624ps     1.219V     1.109V     237.6mV
688ps     1.228V     1.109V     19.6mV
776ps     278.6mV    1.109V     4.207mV
834ps     35.63mV    1.114V     2.684mV
938ps     4.535mV    1.063V     1.669mV
1.014ns   2.35mV     296.6mV    1.243mV
1.082ns   1.746mV    38.21mV    999.4uV
2.38ns    141.3uV    242.9uV    57.11uV
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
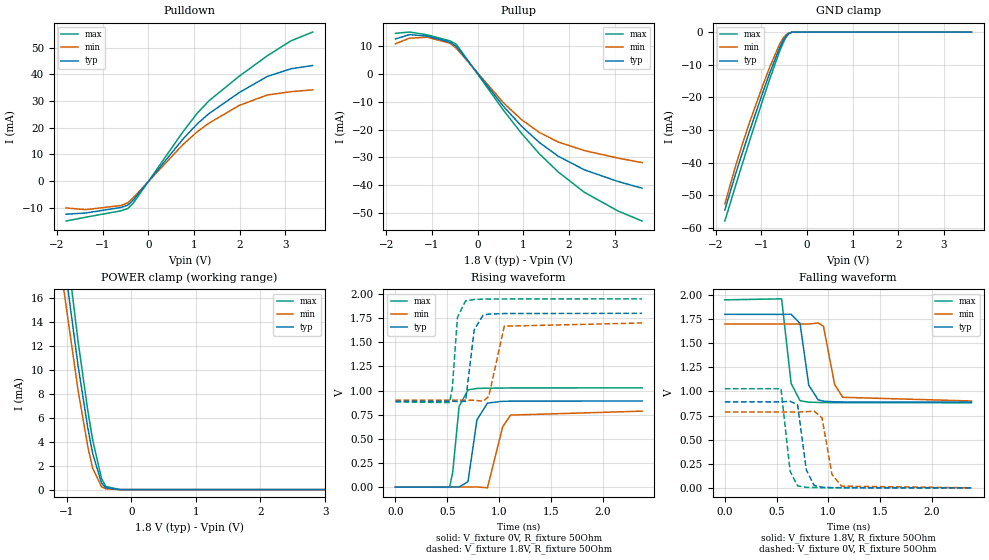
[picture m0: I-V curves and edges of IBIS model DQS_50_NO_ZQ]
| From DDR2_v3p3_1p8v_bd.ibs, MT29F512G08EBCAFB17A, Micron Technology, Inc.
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| MODEL DQS_50_NO_ZQ (50 Ohm Data Strobe I/O with no ODT, With No Cal)
[Model]   DQS_50_NO_ZQ
Model_type   I/O
Vinl = 650.000mV
Vinh = 1.150V
Vmeas = 900.000mV
Vref = 900.000mV
Cref = 0.0pF
Rref = 50.000Ohm
|   typ   min   max
|C_comp   1.200pF   1.100pF   1.300pF
C_comp_pullup   0.6000pF   0.5500pF   0.6500pF
C_comp_pulldown   0.6000pF   0.5500pF   0.6500pF
[Model Spec]
| Input threshold voltage corners
Vinl   0.6500V   0.6000V   0.7250V
Vinh   1.1500V   1.1000V   1.2250V
| Measurement voltage corners
Vmeas   0.9000V   0.8500V   0.9750V
| Timing spec test load voltage corners
Vref   0.9000V   0.8500V   0.9750V
| Dynamic Overshoot Parameters from ONFI4 Specification
D_overshoot_ampl_h   1.00   NA   NA
D_overshoot_ampl_l   1.00   NA   NA
D_overshoot_area_h   0.75n   NA   NA
D_overshoot_area_l   0.75n   NA   NA
[Receiver Thresholds]
|Vth   =  0.900V
|Vth_min  =  0.8820V
|Vth_max  =  0.9180V
|Vinh_ac  =  0.250V
|Vinh_dc  =  0.125V
|Vinl_ac  = -0.250V
|Vinl_dc  = -0.125V
|Tslew_ac =  5.000ns |Not specified, so set to high value
|Threshold_sensitivity = 0.50
|Reference_supply Pullup_ref
Vcross_low   = 0.725V
Vcross_high  = 1.075V
Vdiff_ac   = 500mV
Vdiff_dc   = 250mV
Tdiffslew_ac = 10.000ns |Not specified, so set to high value
[Voltage Range]   1.8000V   1.7000V   1.9500V
[Pullup Reference]   1.8000V   1.7000V   1.9500V
| Junction Temperature (Ambient temp is 35C typ, 70C min, 0C max)
[Temperature Range]   50.0   85.0   0.0
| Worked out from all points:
|   slope of the pulldown table from 0 to 0.27 V, typ, clamps not added: 46.9 ohm
|   slope of the pullup table from 0 to 0.27 V, typ, clamps not added: 47.2 ohm
|   GND clamp passes 1 mA (typ) near -0.45 V on its own axis
|   POWER clamp passes 1 mA (typ) near -0.50 V on its own axis
|   falling waveform, V_fixture 1.8V, R_fixture 50Ohm: 20-80 % time 71.6ps typ, 83.6ps min, 61.1ps max; typ from 1.8 V to 0.889 V
|   rising waveform, V_fixture 0V, R_fixture 50Ohm: 20-80 % time 70.2ps typ, 90.2ps min, 54.6ps max; typ from 0 V to 0.892 V
|   rising waveform, V_fixture 1.8V, R_fixture 50Ohm: 20-80 % time 50.4ps typ, 60.5ps min, 41.9ps max; typ from 0.889 V to 1.8 V
|   falling waveform, V_fixture 0V, R_fixture 50Ohm: 20-80 % time 62.8ps typ, 72.8ps min, 54.5ps max; typ from 0.892 V to 0 V
[Pulldown]
|   Voltage   I(typ)   I(min)   I(max)
-1.8V     -12.5mA    -10.15mA   -15.05mA
-1.37V    -12.04mA   -10.79mA   -13.62mA
-598.1mV  -9.956mA   -9.21mA    -11.22mA
-450.2mV  -9.093mA   -8.215mA   -10.38mA
-331.7mV  -7.173mA   -6.308mA   -8.377mA
765.3mV   15.86mA    13.79mA    18.65mA
1.075V    21.52mA    18.55mA    25.5mA
1.326V    25.25mA    21.66mA    30.07mA
1.985V    33.13mA    28.32mA    39.26mA
2.603V    39.23mA    32.26mA    46.97mA
3.124V    42.12mA    33.51mA    52.61mA
3.6V      43.34mA    34.2mA     55.91mA
[GND Clamp]
|   Voltage   I(typ)   I(min)   I(max)
-1.8V     -54.56mA   -52.69mA   -57.93mA
-1.562V   -43.4mA    -40.96mA   -46.99mA
-1.429V   -37.59mA   -34.94mA   -41mA
-1.266V   -30.68mA   -28.04mA   -33.72mA
-952.2mV  -17.87mA   -15.76mA   -20.1mA
-822.5mV  -12.81mA   -10.99mA   -14.66mA
-599.8mV  -4.844mA   -3.701mA   -5.917mA
-525mV    -2.658mA   -1.9mA     -3.429mA
-462.3mV  -1.283mA   -878.8uA   -1.669mA
-397.8mV  -408.4uA   -316.9uA   -501uA
-322.2mV  -17.1uA    -69.38uA   0A
3.604V    0A         0A         0A
[Pullup]
|   Voltage   I(typ)   I(min)   I(max)
-1.8V     12.64mA    10.92mA    14.66mA
-1.494V   14.2mA     12.91mA    15.13mA
-1.102V   13.66mA    13.25mA    14.12mA
-599.8mV  11.4mA     11.06mA    11.92mA
-462.3mV  9.867mA    9.209mA    10.58mA
576.6mV   -11.83mA   -10.55mA   -13.26mA
962.5mV   -18.77mA   -16.42mA   -21.38mA
1.353V    -24.65mA   -21.01mA   -28.72mA
1.765V    -29.56mA   -24.44mA   -35.23mA
2.338V    -34.45mA   -27.51mA   -42.55mA
3.076V    -38.66mA   -30.23mA   -49.27mA
3.6V      -41.04mA   -31.85mA   -52.85mA
[POWER Clamp]
|   Voltage   I(typ)   I(min)   I(max)
-1.8V     59.37mA    57.52mA    61.9mA
-1.591V   46.25mA    44.06mA    49.53mA
-1.436V   37.64mA    34.94mA    41.24mA
-1.215V   26.85mA    23.86mA    30.17mA
-1.095V   21.42mA    18.62mA    24.4mA
-824.2mV  10.35mA    8.287mA    12.39mA
-672.9mV  5.125mA    3.568mA    6.58mA
-599.8mV  3.04mA     1.802mA    4.182mA
-462.1mV  554.9uA    243.4uA    940.1uA
-396mV    138.1uA    64.45uA    266.2uA
-178.2mV  714nA      206.6nA    547.3nA
3.604V    0A         0A         0A
[Ramp]
R_load = 50
|   typ   min   max
dV/dt_r 5.3523E-01/7.0119E-11   4.7192E-01/9.0196E-11   6.1686E-01/5.4437E-11
dV/dt_f 5.4672E-01/7.1389E-11   4.7943E-01/8.3486E-11   6.4049E-01/6.0993E-11
[Falling Waveform]
V_fixture = 1.8V
V_fixture_min = 1.7V
V_fixture_max = 1.95V
R_fixture = 50Ohm
C_fixture = 0F
|   Time   V(typ)   V(min)   V(max)
0s        1.8V       1.7V       1.95V
548ps     1.799V     1.7V       1.96V
640ps     1.801V     1.7V       1.082V
726ps     1.705V     1.699V     903.9mV
810ps     1.065V     1.699V     888.6mV
900ps     913.3mV    1.71V      885.6mV
952ps     899.1mV    1.676V     884.7mV
1.06ns    892.1mV    1.071V     883.8mV
1.138ns   890.8mV    939.2mV    883.5mV
2.38ns    888.8mV    900.9mV    882.5mV
[Rising Waveform]
V_fixture = 0V
V_fixture_min = 0V
V_fixture_max = 0V
R_fixture = 50Ohm
C_fixture = 0F
|   Time   V(typ)   V(min)   V(max)
0s        85.56uV    160.6uV    23.59uV
522ps     345.8uV    112.6uV    -2.465mV
552ps     1.183mV    108uV      151.2mV
614ps     831.9uV    67.47uV    835.2mV
700ps     56.53mV    481.8uV    1.007V
786ps     696.4mV    1.827mV    1.022V
888ps     870.3mV    -8mV       1.025V
1.034ns   888.8mV    623.4mV    1.026V
1.11ns    890mV      745.6mV    1.027V
2.38ns    892.1mV    786.7mV    1.028V
[Rising Waveform]
V_fixture = 1.8V
V_fixture_min = 1.7V
V_fixture_max = 1.95V
R_fixture = 50Ohm
C_fixture = 0F
|   Time   V(typ)   V(min)   V(max)
0s        888.7mV    900.8mV    882.5mV
522ps     888.9mV    900.7mV    875.7mV
548ps     889.1mV    900.7mV    1.022V
598ps     886.5mV    900.6mV    1.758V
676ps     888.6mV    900.7mV    1.929V
760ps     1.631V     899.6mV    1.944V
846ps     1.781V     888.8mV    1.947V
900ps     1.792V     939mV      1.948V
1.05ns    1.798V     1.667V     1.949V
2.38ns    1.8V       1.7V       1.95V
[Falling Waveform]
|Gnd
V_fixture = 0V
V_fixture_min = 0V
V_fixture_max = 0V
R_fixture = 50Ohm
C_fixture = 0F
|   Time   V(typ)   V(min)   V(max)
0s        892.2mV    786.8mV    1.028V
542ps     891.7mV    786.9mV    1.028V
630ps     898.2mV    787mV      172.8mV
702ps     862.4mV    786.4mV    20.31mV
786ps     187.6mV    789.8mV    5.158mV
862ps     25.26mV    795.8mV    3.092mV
938ps     6.294mV    725.1mV    2.035mV
1.034ns   2.557mV    139.9mV    1.419mV
1.126ns   1.644mV    17.88mV    1.084mV
2.38ns    171.2uV    281.9uV    79.04uV
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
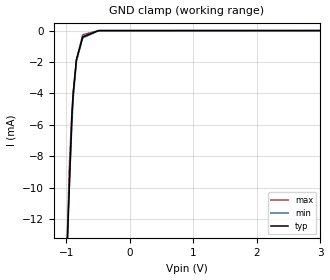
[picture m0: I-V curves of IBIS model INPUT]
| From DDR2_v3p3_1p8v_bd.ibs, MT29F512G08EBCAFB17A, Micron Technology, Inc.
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| MODEL INPUT (Input Input Model)
[Model]   INPUT
Model_type   Input
Vinl = 650.000mV
Vinh = 1.150V
|   typ   min   max
|C_comp   2.050pF   1.950pF   2.150pF
C_comp_power_clamp   1.0250pF   0.9750pF   1.0750pF
C_comp_gnd_clamp   1.0250pF   0.9750pF   1.0750pF
[Model Spec]
| Input threshold voltage corners
Vinl   0.6500V   0.6000V   0.7250V
Vinh   1.1500V   1.1000V   1.2250V
| Dynamic Overshoot Parameters from ONFI4 Specification
D_overshoot_ampl_h   1.00   NA   NA
D_overshoot_ampl_l   1.00   NA   NA
D_overshoot_area_h   3.0n   NA   NA
D_overshoot_area_l   3.0n   NA   NA
[Receiver Thresholds]
Vth   =  0.900V
Vth_min  =  0.8820V
Vth_max  =  0.9180V
Vinh_ac  =  0.250V
Vinh_dc  =  0.125V
Vinl_ac  = -0.250V
Vinl_dc  = -0.125V
Tslew_ac =  5.000ns |Not specified, so set to high value
Threshold_sensitivity = 0.50
Reference_supply Power_clamp_ref
[Voltage Range]   1.8000V   1.7000V   1.9500V
[POWER Clamp Reference]   1.8000V   1.7000V   1.9500V
| Junction Temperature (Ambient temp is 35C typ, 70C min, 0C max)
[Temperature Range]   50.0   85.0   0.0
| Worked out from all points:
|   GND clamp passes 1 mA (typ) near -0.80 V on its own axis
[GND Clamp]
|   Voltage   I(typ)   I(min)   I(max)
-1.8V     -137.9mA   -123.9mA   -159.5mA
-1.06V    -23.14mA   -21.24mA   -24.59mA
-1.05V    -21.83mA   -20.09mA   -23.01mA
-1.04V    -20.52mA   -18.94mA   -21.45mA
-1.03V    -19.21mA   -17.79mA   -19.91mA
-950mV    -9.795mA   -9.676mA   -8.492mA
-910mV    -5.326mA   -5.887mA   -5.166mA
-890mV    -3.979mA   -4.329mA   -3.934mA
-840mV    -1.849mA   -1.953mA   -1.905mA
-740mV    -398.4uA   -466.2uA   -265.1uA
-490mV    -3.609uA   -5.756uA   -433.7nA
3.6V      0A         0A         0A
[POWER Clamp]
|   Voltage   I(typ)   I(min)   I(max)
-1.8V     0A         0A         0A
0V        0A         0A         0A
3.6V      0A         0A         0A
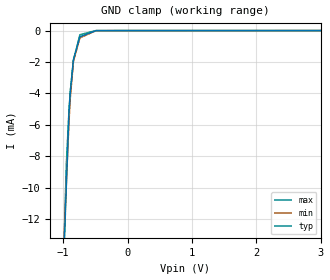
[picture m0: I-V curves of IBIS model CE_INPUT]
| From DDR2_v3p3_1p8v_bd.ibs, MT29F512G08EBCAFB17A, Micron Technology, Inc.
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| MODEL CE_INPUT (CE Input Model)
[Model]   CE_INPUT
Model_type   Input
Vinl = 360.000mV
Vinh = 1.440V
|   typ   min   max
|C_comp   2.100pF   2.000pF   2.200pF
C_comp_power_clamp   1.0500pF   1.0000pF   1.1000pF
C_comp_gnd_clamp   1.0500pF   1.0000pF   1.1000pF
[Model Spec]
| Input threshold voltage corners
Vinl   0.3600V   0.3400V   0.3900V
Vinh   1.4400V   1.3600V   1.5600V
| Dynamic Overshoot Parameters from ONFI4 Specification
D_overshoot_ampl_h   1.00   NA   NA
D_overshoot_ampl_l   1.00   NA   NA
D_overshoot_area_h   3.0n   NA   NA
D_overshoot_area_l   3.0n   NA   NA
[Voltage Range]   1.8000V   1.7000V   1.9500V
| Junction Temperature (Ambient temp is 35C typ, 70C min, 0C max)
[Temperature Range]   50.0   85.0   0.0
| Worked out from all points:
|   GND clamp passes 1 mA (typ) near -0.80 V on its own axis
[GND Clamp]
|   Voltage   I(typ)   I(min)   I(max)
-1.8V     -137.9mA   -123.9mA   -159.5mA
-1.06V    -23.14mA   -21.24mA   -24.59mA
-1.05V    -21.83mA   -20.09mA   -23.01mA
-1.04V    -20.52mA   -18.94mA   -21.45mA
-1.03V    -19.21mA   -17.79mA   -19.91mA
-950mV    -9.795mA   -9.676mA   -8.492mA
-910mV    -5.326mA   -5.887mA   -5.166mA
-890mV    -3.979mA   -4.329mA   -3.934mA
-840mV    -1.849mA   -1.953mA   -1.905mA
-740mV    -398.4uA   -466.2uA   -265.1uA
-490mV    -3.609uA   -5.756uA   -433.7nA
3.6V      0A         0A         0A
[POWER Clamp]
|   Voltage   I(typ)   I(min)   I(max)
-1.8V     0A         0A         0A
0V        0A         0A         0A
3.6V      0A         0A         0A
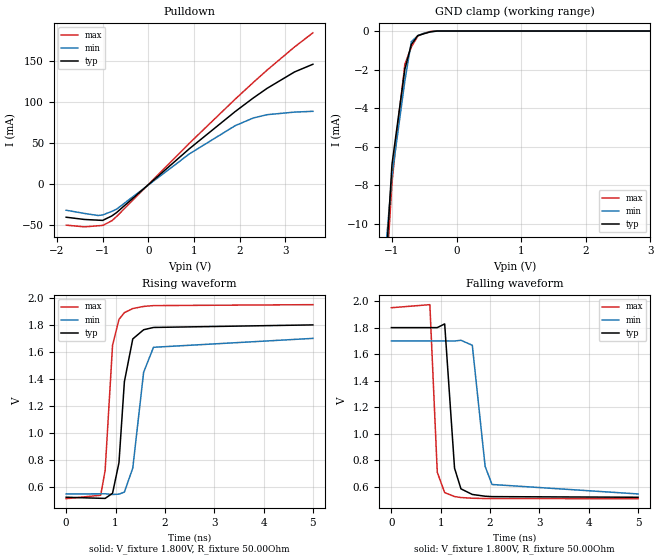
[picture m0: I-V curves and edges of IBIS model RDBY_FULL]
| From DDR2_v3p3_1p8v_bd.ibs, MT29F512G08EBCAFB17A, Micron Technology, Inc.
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| MODEL RDBY_FULL (FULL-Drv RDBY Open-Drain Model)
[Model]   RDBY_FULL
Model_type   Open_drain
Vmeas = 0.900V
Vref = 1.800V
Cref = 50.0pF
Rref = 1000.000Ohm
|   typ   min   max
|C_comp   2.200pF   2.100pF   2.300pF
C_comp_pulldown   2.2000pF   2.1000pF   2.3000pF
[Model Spec]
| Measurement voltage corners
Vmeas   0.900V   0.850V   0.975V
| Timing spec test load voltage corners
Vref   1.800V   1.700V   1.950V
[Voltage Range]   1.8000V   1.7000V   1.9500V
| Junction Temperature (Ambient temp is 35C typ, 70C min, 0C max)
[Temperature Range]   50.0   85.0   0.0
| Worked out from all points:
|   slope of the pulldown table from 0 to 0.27 V, typ, clamps not added: 20.3 ohm
|   GND clamp passes 1 mA (typ) near -0.72 V on its own axis
|   falling waveform, V_fixture 1.800V, R_fixture 50.00Ohm: 20-80 % time 110ps typ, 175ps min, 80.4ps max; typ from 1.8 V to 0.522 V
|   rising waveform, V_fixture 1.800V, R_fixture 50.00Ohm: 20-80 % time 162ps typ, 211ps min, 140ps max; typ from 0.522 V to 1.8 V
[Pulldown]
|   Voltage   I(typ)   I(min)   I(max)
-1.8V     -39.94mA   -31.44mA   -49.57mA
-1.4V     -42.67mA   -35.33mA   -51.65mA
-1.1V     -43.53mA   -37.88mA   -50.34mA
-1V       -43.81mA   -37.17mA   -49.9mA
-800mV    -38.35mA   -32.85mA   -44.26mA
-700mV    -34.45mA   -30.27mA   -39.27mA
900mV     43.49mA    37.16mA    50.18mA
1.9V      88.51mA    71.38mA    103.6mA
2.3V      105.2mA    80.77mA    124.1mA
2.6V      116.8mA    84.71mA    139mA
3.2V      136.7mA    87.86mA    167.1mA
3.6V      146mA      88.79mA    184.2mA
[GND Clamp]
|   Voltage   I(typ)   I(min)   I(max)
-1.8V     -53.16mA   -50.88mA   -56.12mA
-1.1V     -12.51mA   -11.47mA   -13.42mA
-1V       -6.937mA   -7.518mA   -7.897mA
-900mV    -4.444mA   -5.049mA   -4.587mA
-800mV    -1.974mA   -2.58mA    -1.717mA
-700mV    -696.2uA   -550.2uA   -828.6uA
-600mV    -234.8uA   -242.9uA   -259.5uA
-500mV    -135.2uA   -103.3uA   -114.7uA
-400mV    -35.55uA   -48.43uA   -16.79uA
-300mV    0A         0A         0A
3.6V      0A         0A         0A
[POWER Clamp]
|   Voltage   I(typ)   I(min)   I(max)
-1.8V     0A         0A         0A
0V        0A         0A         0A
3.6V      0A         0A         0A
[Ramp]
R_load = 50.00Ohm
|   typ   min   max
dV/dt_r   766.597mV/162.342ps 691.596mV/210.999ps 863.047mV/140.287ps
dV/dt_f   766.597mV/110.004ps 691.596mV/175.417ps 863.047mV/80.423ps
[Falling Waveform]
V_fixture = 1.800V
V_fixture_min = 1.700V
V_fixture_max = 1.950V
R_fixture = 50.00Ohm
|   Time   V(typ)   V(min)   V(max)
0s        1.8V       1.7V       1.95V
780ps     1.8V       1.7V       1.973V
930ps     1.8V       1.7V       711.1mV
1.08ns    1.828V     1.7V       557.4mV
1.28ns    741.4mV    1.699V     527.8mV
1.41ns    585.8mV    1.705V     520.4mV
1.64ns    543.5mV    1.667V     515mV
1.9ns     530.2mV    754.7mV    513mV
2.04ns    527.2mV    618.6mV    512.5mV
5ns       522.4mV    547.4mV    511.7mV
[Rising Waveform]
V_fixture = 1.800V
V_fixture_min = 1.700V
V_fixture_max = 1.950V
R_fixture = 50.00Ohm
|   Time   V(typ)   V(min)   V(max)
0s        522.4mV    547.4mV    511.7mV
700ps     514.5mV    547.5mV    537.3mV
790ps     513.8mV    548mV      721.5mV
940ps     551.6mV    542.6mV    1.649V
1.07ns    778.3mV    545.4mV    1.841V
1.18ns    1.379V     560.7mV    1.891V
1.35ns    1.696V     738.6mV    1.921V
1.57ns    1.764V     1.449V     1.937V
1.77ns    1.781V     1.634V     1.943V
5ns       1.8V       1.7V       1.95V
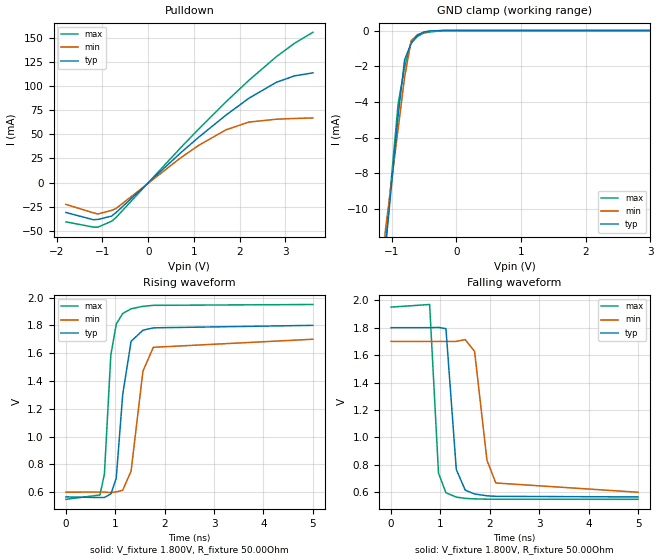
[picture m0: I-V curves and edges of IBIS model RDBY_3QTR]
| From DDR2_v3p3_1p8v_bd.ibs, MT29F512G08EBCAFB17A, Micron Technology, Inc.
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| MODEL RDBY_3QTR (3QTR-Drv RDBY Open-Drain Model)
[Model]   RDBY_3QTR
Model_type   Open_drain
Vmeas = 0.900V
Vref = 1.800V
Cref = 50.0pF
Rref = 1000.000Ohm
|   typ   min   max
|C_comp   2.200pF   2.100pF   2.300pF
C_comp_pulldown   2.2000pF   2.1000pF   2.3000pF
[Model Spec]
| Measurement voltage corners
Vmeas   0.900V   0.850V   0.975V
| Timing spec test load voltage corners
Vref   1.800V   1.700V   1.950V
[Voltage Range]   1.8000V   1.7000V   1.9500V
| Junction Temperature (Ambient temp is 35C typ, 70C min, 0C max)
[Temperature Range]   50.0   85.0   0.0
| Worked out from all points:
|   slope of the pulldown table from 0 to 0.27 V, typ, clamps not added: 22.6 ohm
|   GND clamp passes 1 mA (typ) near -0.73 V on its own axis
|   falling waveform, V_fixture 1.800V, R_fixture 50.00Ohm: 20-80 % time 120ps typ, 197ps min, 87.8ps max; typ from 1.8 V to 0.566 V
|   rising waveform, V_fixture 1.800V, R_fixture 50.00Ohm: 20-80 % time 160ps typ, 206ps min, 138ps max; typ from 0.566 V to 1.8 V
[Pulldown]
|   Voltage   I(typ)   I(min)   I(max)
-1.8V     -30.95mA   -22.56mA   -40.66mA
-1.2V     -38.46mA   -31.31mA   -46.09mA
-1.1V     -38.17mA   -32.53mA   -46.16mA
-800mV    -34.69mA   -28.79mA   -40.01mA
-700mV    -30.93mA   -26.72mA   -36mA
700mV     30.43mA    25.37mA    35.63mA
1.1V      46.89mA    38.48mA    55.34mA
1.7V      69.92mA    54.68mA    83.68mA
2.2V      87.36mA    62.7mA     105.9mA
2.8V      103.9mA    65.67mA    130.4mA
3.2V      110.6mA    66.46mA    144.4mA
3.6V      113.7mA    66.97mA    155.7mA
[GND Clamp]
|   Voltage   I(typ)   I(min)   I(max)
-1.8V     -53.16mA   -50.88mA   -56.12mA
-1.1V     -12.37mA   -11.29mA   -12.17mA
-1V       -8.561mA   -8.396mA   -8.114mA
-900mV    -4.752mA   -5.506mA   -4.097mA
-800mV    -1.643mA   -2.615mA   -2.055mA
-700mV    -725uA     -578.2uA   -680.3uA
-600mV    -274.9uA   -229.1uA   -324.8uA
-500mV    -75.33uA   -104.9uA   -134.2uA
-400mV    -22.6uA    -27.43uA   -78.78uA
-200mV    0A         0A         0A
3.6V      0A         0A         0A
[POWER Clamp]
|   Voltage   I(typ)   I(min)   I(max)
-1.8V     0A         0A         0A
0V        0A         0A         0A
3.6V      0A         0A         0A
[Ramp]
R_load = 50.00Ohm
|   typ   min   max
dV/dt_r   740.543mV/160.082ps 660.086mV/205.694ps 841.051mV/138.175ps
dV/dt_f   740.543mV/120.138ps 660.086mV/196.973ps 841.051mV/87.756ps
[Falling Waveform]
V_fixture = 1.800V
V_fixture_min = 1.700V
V_fixture_max = 1.950V
R_fixture = 50.00Ohm
|   Time   V(typ)   V(min)   V(max)
0s        1.8V       1.7V       1.95V
780ps     1.8V       1.7V       1.969V
960ps     1.802V     1.7V       738.8mV
1.11ns    1.793V     1.7V       596.4mV
1.32ns    765.8mV    1.7V       564.4mV
1.5ns     615.4mV    1.713V     555.4mV
1.69ns    587.3mV    1.627V     551.5mV
1.94ns    574mV      834.2mV    549.6mV
2.12ns    570.2mV    667.5mV    549.1mV
5ns       565.8mV    599.9mV    548.3mV
[Rising Waveform]
V_fixture = 1.800V
V_fixture_min = 1.700V
V_fixture_max = 1.950V
R_fixture = 50.00Ohm
|   Time   V(typ)   V(min)   V(max)
0s        565.8mV    599.9mV    548.3mV
690ps     561.1mV    600.1mV    579.4mV
780ps     561.9mV    600.4mV    730mV
910ps     586.8mV    596.8mV    1.586V
1.02ns    701mV      601.6mV    1.809V
1.15ns    1.301V     613.6mV    1.885V
1.32ns    1.685V     751.4mV    1.919V
1.56ns    1.765V     1.47V      1.937V
1.77ns    1.782V     1.642V     1.944V
5ns       1.8V       1.7V       1.95V
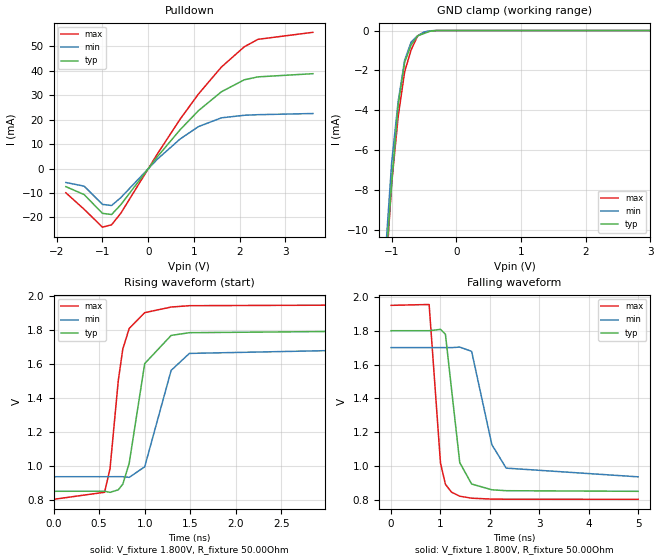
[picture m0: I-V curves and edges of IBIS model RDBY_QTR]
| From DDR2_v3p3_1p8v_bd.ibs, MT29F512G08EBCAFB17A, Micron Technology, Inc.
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| MODEL RDBY_QTR (QTR-Drv RDBY Open-Drain Model)
[Model]   RDBY_QTR
Model_type   Open_drain
Vmeas = 0.900V
Vref = 1.800V
Cref = 50.0pF
Rref = 1000.000Ohm
|   typ   min   max
|C_comp   2.200pF   2.100pF   2.300pF
C_comp_pulldown   2.2000pF   2.1000pF   2.3000pF
[Model Spec]
| Measurement voltage corners
Vmeas   0.900V   0.850V   0.975V
| Timing spec test load voltage corners
Vref   1.800V   1.700V   1.950V
[Voltage Range]   1.8000V   1.7000V   1.9500V
| Junction Temperature (Ambient temp is 35C typ, 70C min, 0C max)
[Temperature Range]   50.0   85.0   0.0
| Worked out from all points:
|   slope of the pulldown table from 0 to 0.27 V, typ, clamps not added: 41.6 ohm
|   GND clamp passes 1 mA (typ) near -0.73 V on its own axis
|   falling waveform, V_fixture 1.800V, R_fixture 50.00Ohm: 20-80 % time 205ps typ, 344ps min, 148ps max; typ from 1.8 V to 0.85 V
|   rising waveform, V_fixture 1.800V, R_fixture 50.00Ohm: 20-80 % time 167ps typ, 215ps min, 144ps max; typ from 0.85 V to 1.8 V
[Pulldown]
|   Voltage   I(typ)   I(min)   I(max)
-1.8V     -7.4mA     -5.705mA   -9.922mA
-1.4V     -10.66mA   -7.208mA   -16.68mA
-1V       -18.33mA   -14.67mA   -23.98mA
-800mV    -18.8mA    -15.11mA   -23.01mA
-600mV    -14.81mA   -11.91mA   -18.33mA
200mV     4.839mA    3.836mA    5.984mA
700mV     15.94mA    12.14mA    20.27mA
1.1V      23.72mA    17.18mA    30.54mA
1.6V      31.42mA    20.76mA    41.54mA
2.1V      36.33mA    21.81mA    49.84mA
2.4V      37.53mA    22.05mA    52.89mA
3.6V      38.83mA    22.53mA    55.76mA
[GND Clamp]
|   Voltage   I(typ)   I(min)   I(max)
-1.8V     -53.16mA   -50.88mA   -56.12mA
-1.1V     -12.07mA   -11.36mA   -12.7mA
-1V       -7.648mA   -6.613mA   -7.652mA
-900mV    -3.751mA   -3.56mA    -4.33mA
-800mV    -1.599mA   -1.496mA   -2.071mA
-700mV    -723.2uA   -581.7uA   -976.9uA
-600mV    -269uA     -266.2uA   -270.6uA
-500mV    -148.4uA   -71.95uA   -95.31uA
-400mV    -27.73uA   -12.46uA   -22.07uA
-300mV    -45.47nA   0A         0A
3.6V      0A         0A         0A
[POWER Clamp]
|   Voltage   I(typ)   I(min)   I(max)
-1.8V     0A         0A         0A
0V        0A         0A         0A
3.6V      0A         0A         0A
[Ramp]
R_load = 50.00Ohm
|   typ   min   max
dV/dt_r   569.935mV/166.913ps 458.535mV/215.005ps 688.366mV/144.022ps
dV/dt_f   569.935mV/204.642ps 458.535mV/344.408ps 688.366mV/148.452ps
[Falling Waveform]
V_fixture = 1.800V
V_fixture_min = 1.700V
V_fixture_max = 1.950V
R_fixture = 50.00Ohm
|   Time   V(typ)   V(min)   V(max)
0s        1.8V       1.7V       1.95V
770ps     1.8V       1.7V       1.955V
1ns       1.808V     1.7V       1.017V
1.1ns     1.779V     1.7V       891.8mV
1.22ns    1.464V     1.7V       845.7mV
1.39ns    1.02V      1.703V     821.3mV
1.63ns    893.4mV    1.678V     809.5mV
2.04ns    859.3mV    1.126V     804.2mV
2.33ns    853.8mV    987.3mV    803.4mV
5ns       850.2mV    935.9mV    802.8mV
[Rising Waveform]
V_fixture = 1.800V
V_fixture_min = 1.700V
V_fixture_max = 1.950V
R_fixture = 50.00Ohm
|   Time   V(typ)   V(min)   V(max)
0s        850.2mV    935.9mV    802.8mV
560ps     850.6mV    936mV      844.4mV
620ps     843.9mV    936mV      984.7mV
710ps     858.8mV    936.3mV    1.501V
760ps     892.1mV    936mV      1.688V
830ps     1.015V     932.2mV    1.809V
1ns       1.602V     994.4mV    1.902V
1.29ns    1.768V     1.562V     1.935V
1.49ns    1.784V     1.662V     1.943V
5ns       1.8V       1.7V       1.95V
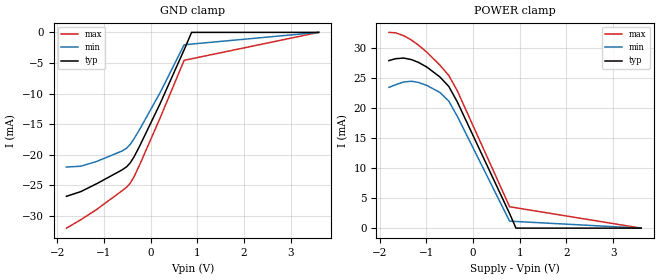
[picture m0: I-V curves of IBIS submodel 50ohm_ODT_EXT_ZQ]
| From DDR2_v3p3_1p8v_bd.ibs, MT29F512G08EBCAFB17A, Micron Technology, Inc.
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| SUBMODEL 50ohm_ODT_EXT_ZQ
[Submodel]   50ohm_ODT_EXT_ZQ
Submodel_type  Dynamic_clamp
[GND Clamp]
|   Voltage   I(typ)   I(min)   I(max)
-1.8V     -26.77mA   -21.99mA   -31.97mA
-1.494V   -26.01mA   -21.86mA   -30.61mA
-1.153V   -24.72mA   -21.08mA   -28.92mA
-604.5mV  -22.44mA   -19.36mA   -25.84mA
-510mV    -21.94mA   -18.9mA    -25.27mA
-432mV    -21.29mA   -18.27mA   -24.61mA
-352.5mV  -20.33mA   -17.38mA   -23.59mA
-228mV    -18.5mA    -15.79mA   -21.55mA
203mV     -11.68mA   -9.88mA    -14.03mA
719.5mV   -2.858mA   -2.025mA   -4.567mA
880mV     0A         NA         NA
3.6V      0A         0A         0A
[POWER Clamp]
|   Voltage   I(typ)   I(min)   I(max)
-1.8V     27.98mA    23.51mA    32.69mA
-1.659V   28.29mA    23.94mA    32.62mA
-1.486V   28.4mA     24.4mA     32.15mA
-1.315V   28.14mA    24.53mA    31.39mA
-1.169V   27.68mA    24.33mA    30.56mA
-989mV    26.9mA     23.83mA    29.38mA
-709mV    25.25mA    22.66mA    27.23mA
-519.5mV  23.67mA    21.22mA    25.51mA
-338.5mV  21.12mA    18.71mA    22.97mA
784mV     2.426mA    1.168mA    3.569mA
920mV     0A         NA         NA
3.6V      0A         0A         0A
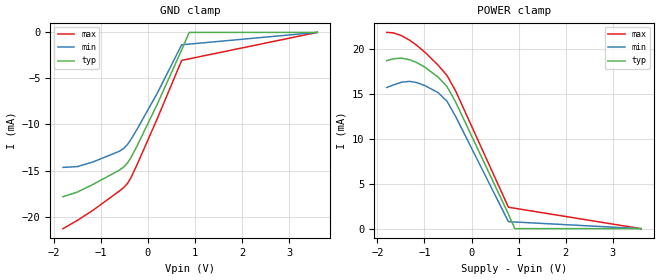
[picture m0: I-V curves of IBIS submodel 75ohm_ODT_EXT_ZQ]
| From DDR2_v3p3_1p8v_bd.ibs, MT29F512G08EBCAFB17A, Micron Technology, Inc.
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| SUBMODEL 75ohm_ODT_EXT_ZQ
[Submodel]   75ohm_ODT_EXT_ZQ
Submodel_type  Dynamic_clamp
[GND Clamp]
|   Voltage   I(typ)   I(min)   I(max)
-1.8V     -17.84mA   -14.66mA   -21.31mA
-1.494V   -17.34mA   -14.57mA   -20.41mA
-1.154V   -16.48mA   -14.05mA   -19.28mA
-604.5mV  -14.96mA   -12.91mA   -17.23mA
-510mV    -14.62mA   -12.6mA    -16.85mA
-432mV    -14.19mA   -12.18mA   -16.41mA
-352.5mV  -13.55mA   -11.59mA   -15.73mA
-228mV    -12.34mA   -10.53mA   -14.37mA
203.5mV   -7.78mA    -6.583mA   -9.35mA
720mV     -1.9mA     -1.345mA   -3.039mA
880mV     0A         NA         NA
3.6V      0A         0A         0A
[POWER Clamp]
|   Voltage   I(typ)   I(min)   I(max)
-1.8V     18.66mA    15.68mA    21.8mA
-1.659V   18.87mA    15.96mA    21.75mA
-1.486V   18.94mA    16.27mA    21.44mA
-1.314V   18.76mA    16.36mA    20.93mA
-1.167V   18.46mA    16.23mA    20.38mA
-990mV    17.94mA    15.89mA    19.6mA
-709mV    16.83mA    15.11mA    18.16mA
-520mV    15.78mA    14.15mA    17.01mA
-338.5mV  14.08mA    12.48mA    15.31mA
784mV     1.617mA    778.5uA    2.379mA
920mV     0A         NA         NA
3.6V      0A         0A         0A
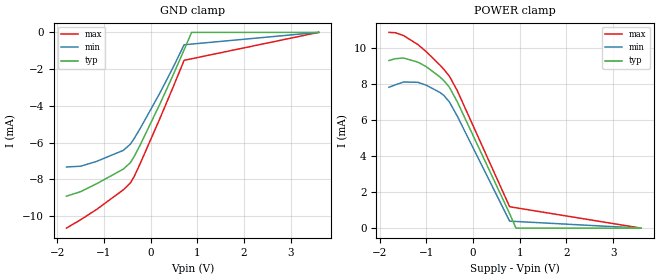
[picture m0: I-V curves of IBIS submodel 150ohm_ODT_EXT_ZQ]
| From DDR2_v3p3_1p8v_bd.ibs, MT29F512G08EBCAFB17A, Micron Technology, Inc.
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| SUBMODEL 150ohm_ODT_EXT_ZQ
[Submodel]   150ohm_ODT_EXT_ZQ
Submodel_type  Dynamic_clamp
[GND Clamp]
|   Voltage   I(typ)   I(min)   I(max)
-1.8V     -8.921mA   -7.33mA    -10.66mA
-1.494V   -8.671mA   -7.287mA   -10.2mA
-1.154V   -8.242mA   -7.026mA   -9.642mA
-581mV    -7.443mA   -6.423mA   -8.57mA
-431.5mV  -7.096mA   -6.087mA   -8.203mA
-352mV    -6.774mA   -5.791mA   -7.861mA
-228.5mV  -6.171mA   -5.266mA   -7.188mA
203.5mV   -3.89mA    -3.291mA   -4.676mA
482mV     -2.333mA   -1.915mA   -2.994mA
719.5mV   -952.6uA   -675.1uA   -1.522mA
880mV     0A         NA         NA
3.6V      0A         0A         0A
[POWER Clamp]
|   Voltage   I(typ)   I(min)   I(max)
-1.8V     9.326mA    7.836mA    10.89mA
-1.659V   9.427mA    7.976mA    10.87mA
-1.486V   9.463mA    8.128mA    10.71mA
-1.179V   9.233mA    8.113mA    10.21mA
-999mV    8.979mA    7.949mA    9.811mA
-706.5mV  8.404mA    7.545mA    9.067mA
-622.5mV  8.199mA    7.379mA    8.829mA
-506mV    7.839mA    7.022mA    8.454mA
-337.5mV  7.034mA    6.234mA    7.652mA
784mV     809uA      389.5uA    1.19mA
920mV     0A         NA         NA
3.6V      0A         0A         0A
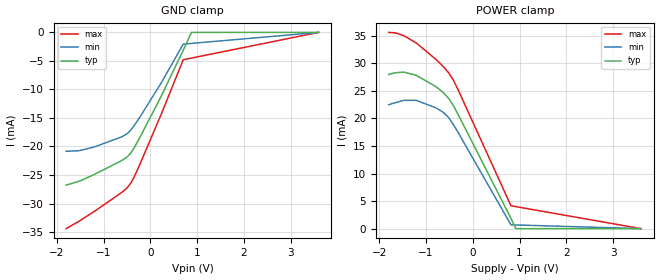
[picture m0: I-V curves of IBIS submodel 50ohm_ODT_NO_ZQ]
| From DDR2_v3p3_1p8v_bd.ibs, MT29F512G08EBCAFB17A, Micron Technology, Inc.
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| SUBMODEL 50ohm_ODT_NO_ZQ
[Submodel]   50ohm_ODT_NO_ZQ
Submodel_type  Dynamic_clamp
[GND Clamp]
|   Voltage   I(typ)   I(min)   I(max)
-1.8V     -26.77mA   -20.85mA   -34.41mA
-1.521V   -26.1mA    -20.74mA   -33.09mA
-1.199V   -24.91mA   -20.09mA   -31.4mA
-611mV    -22.47mA   -18.31mA   -28.06mA
-498mV    -21.85mA   -17.78mA   -27.28mA
-421mV    -21.18mA   -17.16mA   -26.47mA
-347mV    -20.25mA   -16.36mA   -25.37mA
-226mV    -18.47mA   -14.89mA   -23.18mA
231mV     -11.22mA   -8.892mA   -14.4mA
704mV     -3.132mA   -2.054mA   -4.793mA
880mV     0A         NA         NA
3.6V      0A         0A         0A
[POWER Clamp]
|   Voltage   I(typ)   I(min)   I(max)
-1.8V     27.98mA    22.49mA    35.61mA
-1.659V   28.29mA    22.85mA    35.53mA
-1.476V   28.4mA     23.29mA    35.02mA
-1.213V   27.84mA    23.29mA    33.71mA
-788mV    25.76mA    21.92mA    30.72mA
-629mV    24.67mA    21.09mA    29.39mA
-519.5mV  23.67mA    20.18mA    28.32mA
-412.5mV  22.28mA    18.85mA    26.89mA
-308mV    20.62mA    17.36mA    25.08mA
815.5mV   1.869mA    700.7uA    4.157mA
920mV     0A         NA         NA
3.6V      0A         0A         0A
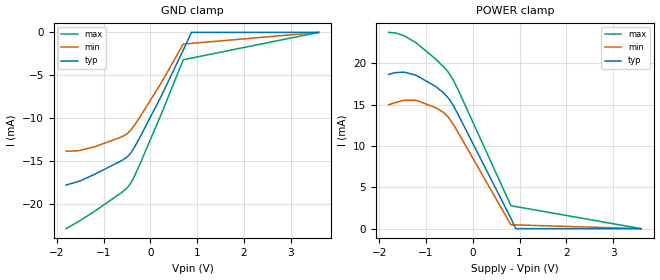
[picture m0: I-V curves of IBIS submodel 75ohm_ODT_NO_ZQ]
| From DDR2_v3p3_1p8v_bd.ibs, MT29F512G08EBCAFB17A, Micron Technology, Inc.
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| SUBMODEL 75ohm_ODT_NO_ZQ
[Submodel]   75ohm_ODT_NO_ZQ
Submodel_type  Dynamic_clamp
[GND Clamp]
|   Voltage   I(typ)   I(min)   I(max)
-1.8V     -17.84mA   -13.9mA    -22.94mA
-1.521V   -17.4mA    -13.82mA   -22.06mA
-1.2V     -16.61mA   -13.39mA   -20.94mA
-611mV    -14.98mA   -12.21mA   -18.71mA
-498mV    -14.57mA   -11.86mA   -18.19mA
-421mV    -14.12mA   -11.44mA   -17.65mA
-347mV    -13.5mA    -10.91mA   -16.91mA
-225.5mV  -12.31mA   -9.921mA   -15.45mA
231.5mV   -7.473mA   -5.924mA   -9.594mA
704mV     -2.088mA   -1.37mA    -3.196mA
880mV     0A         NA         NA
3.6V      0A         0A         0A
[POWER Clamp]
|   Voltage   I(typ)   I(min)   I(max)
-1.8V     18.66mA    14.99mA    23.74mA
-1.659V   18.87mA    15.24mA    23.69mA
-1.476V   18.94mA    15.53mA    23.35mA
-1.213V   18.56mA    15.53mA    22.48mA
-788.5mV  17.18mA    14.62mA    20.49mA
-626mV    16.43mA    14.05mA    19.58mA
-520mV    15.78mA    13.46mA    18.89mA
-413mV    14.86mA    12.57mA    17.93mA
-308.5mV  13.75mA    11.58mA    16.73mA
815mV     1.252mA    472uA      2.777mA
920mV     0A         NA         NA
3.6V      0A         0A         0A
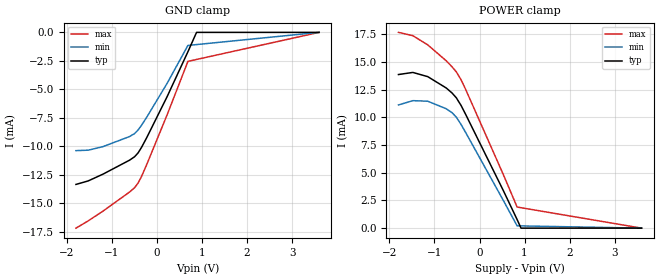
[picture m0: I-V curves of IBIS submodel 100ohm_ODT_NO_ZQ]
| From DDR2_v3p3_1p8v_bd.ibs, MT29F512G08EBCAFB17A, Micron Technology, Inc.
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| SUBMODEL 100ohm_ODT_NO_ZQ
[Submodel]   100ohm_ODT_NO_ZQ
Submodel_type  Dynamic_clamp
[GND Clamp]
|   Voltage   I(typ)   I(min)   I(max)
-1.8V     -13.36mA   -10.39mA   -17.2mA
-1.528V   -13.05mA   -10.35mA   -16.56mA
-1.202V   -12.46mA   -10.04mA   -15.71mA
-611mV    -11.23mA   -9.154mA   -14.03mA
-499mV    -10.93mA   -8.893mA   -13.65mA
-421mV    -10.59mA   -8.579mA   -13.24mA
-347.5mV  -10.13mA   -8.18mA    -12.69mA
-227.5mV  -9.241mA   -7.446mA   -11.6mA
224mV     -5.65mA    -4.481mA   -7.249mA
686.5mV   -1.701mA   -1.147mA   -2.547mA
878mV     0A         NA         NA
3.6V      0A         0A         0A
[POWER Clamp]
|   Voltage   I(typ)   I(min)   I(max)
-1.8V     13.88mA    11.13mA    17.69mA
-1.481V   14.07mA    11.52mA    17.39mA
-1.15V    13.69mA    11.47mA    16.56mA
-741.5mV  12.67mA    10.79mA    15.13mA
-612.5mV  12.22mA    10.44mA    14.59mA
-515.5mV  11.78mA    10.03mA    14.12mA
-409mV    11.08mA    9.363mA    13.4mA
-309.5mV  10.29mA    8.655mA    12.55mA
529.5mV   3.389mA    2.5mA      4.833mA
835mV     775.1uA    208.1uA    1.907mA
922mV     0A         NA         NA
3.6V      0A         0A         0A
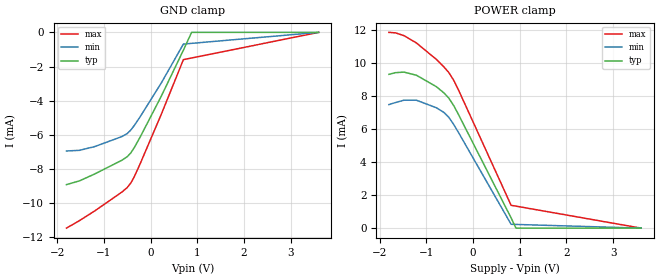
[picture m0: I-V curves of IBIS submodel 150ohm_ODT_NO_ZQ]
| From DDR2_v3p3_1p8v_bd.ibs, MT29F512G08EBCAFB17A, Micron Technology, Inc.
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| SUBMODEL 150ohm_ODT_NO_ZQ
[Submodel]   150ohm_ODT_NO_ZQ
Submodel_type  Dynamic_clamp
[GND Clamp]
|   Voltage   I(typ)   I(min)   I(max)
-1.8V     -8.921mA   -6.949mA   -11.47mA
-1.521V   -8.7mA     -6.912mA   -11.03mA
-1.199V   -8.302mA   -6.695mA   -10.47mA
-610.5mV  -7.488mA   -6.104mA   -9.353mA
-498mV    -7.285mA   -5.928mA   -9.093mA
-420.5mV  -7.057mA   -5.72mA    -8.823mA
-347mV    -6.751mA   -5.455mA   -8.456mA
-226mV    -6.158mA   -4.963mA   -7.728mA
231.5mV   -3.736mA   -2.962mA   -4.797mA
704mV     -1.044mA   -684.9uA   -1.598mA
880mV     0A         NA         NA
3.6V      0A         0A         0A
[POWER Clamp]
|   Voltage   I(typ)   I(min)   I(max)
-1.8V     9.326mA    7.493mA    11.87mA
-1.659V   9.427mA    7.616mA    11.84mA
-1.477V   9.461mA    7.758mA    11.67mA
-1.212V   9.272mA    7.757mA    11.23mA
-784.5mV  8.577mA    7.299mA    10.23mA
-622.5mV  8.199mA    7.015mA    9.775mA
-518.5mV  7.884mA    6.723mA    9.435mA
-411.5mV  7.422mA    6.278mA    8.959mA
-307mV    6.868mA    5.781mA    8.356mA
815.5mV   623.2uA    233.6uA    1.386mA
920mV     0A         NA         NA
3.6V      0A         0A         0A
